###############################################################
#  Generated by:      Cadence Innovus 20.13-s083_1
#  OS:                Linux x86_64(Host ID caddy13)
#  Generated on:      Sun Jul 11 21:08:58 2021
#  Design:            deconv_kernel_estimator_top_level
#  Command:           write_lef_abstract -specifyTopLayer 6 -PGPinLayers {5 6} -noCutObs -stripePin results/deconv_kernel_estimator_top_level.lef
###############################################################

VERSION 5.8 ;

BUSBITCHARS "[]" ;
DIVIDERCHAR "/" ;

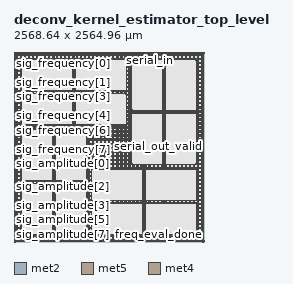
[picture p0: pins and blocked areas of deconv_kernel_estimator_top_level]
MACRO deconv_kernel_estimator_top_level
  CLASS BLOCK ;
  SIZE 2568.640000 BY 2564.960000 ;
  FOREIGN deconv_kernel_estimator_top_level 0.000000 0.000000 ;
  ORIGIN 0 0 ;
  SYMMETRY X Y R90 ;
  PIN clk
    DIRECTION INPUT ;
    USE SIGNAL ;
    ANTENNAPARTIALMETALAREA 6.3938 LAYER met2  ;
    ANTENNAPARTIALMETALSIDEAREA 31.808 LAYER met2  ;
    ANTENNAPARTIALCUTAREA 0.04 LAYER via2  ;
    ANTENNAPARTIALMETALAREA 8.9508 LAYER met3  ;
    ANTENNAPARTIALMETALSIDEAREA 48.208 LAYER met3  ;
    ANTENNAMODEL OXIDE1 ;
    ANTENNAGATEAREA 0.576 LAYER met3  ;
    ANTENNAMAXAREACAR 16.6087 LAYER met3  ;
    ANTENNAMAXSIDEAREACAR 86.8212 LAYER met3  ;
    ANTENNAMAXCUTCAR 0.158681 LAYER via3  ;
    PORT
      LAYER met2 ;
        RECT 1.080000 2564.475000 1.220000 2564.960000 ;
    END
  END clk
  PIN rst_n
    DIRECTION INPUT ;
    USE SIGNAL ;
    ANTENNAPARTIALMETALAREA 73.5824 LAYER met2  ;
    ANTENNAPARTIALMETALSIDEAREA 367.633 LAYER met2  ;
    ANTENNAPARTIALCUTAREA 0.04 LAYER via2  ;
    ANTENNAPARTIALMETALAREA 0.2509 LAYER met3  ;
    ANTENNAPARTIALMETALSIDEAREA 1.808 LAYER met3  ;
    ANTENNAPARTIALCUTAREA 0.04 LAYER via3  ;
    ANTENNAPARTIALMETALAREA 4.3518 LAYER met4  ;
    ANTENNAPARTIALMETALSIDEAREA 23.68 LAYER met4  ;
    ANTENNAMODEL OXIDE1 ;
    ANTENNAGATEAREA 0.495 LAYER met4  ;
    ANTENNAMAXAREACAR 37.3026 LAYER met4  ;
    ANTENNAMAXSIDEAREACAR 189.04 LAYER met4  ;
    ANTENNAMAXCUTCAR 0.265455 LAYER via4  ;
    PORT
      LAYER met2 ;
        RECT 366.780000 2564.475000 366.920000 2564.960000 ;
    END
  END rst_n
  PIN load_en
    DIRECTION INPUT ;
    USE SIGNAL ;
    ANTENNAPARTIALMETALAREA 69.7464 LAYER met2  ;
    ANTENNAPARTIALMETALSIDEAREA 348.453 LAYER met2  ;
    ANTENNAPARTIALCUTAREA 0.04 LAYER via2  ;
    ANTENNAPARTIALMETALAREA 3.505 LAYER met3  ;
    ANTENNAPARTIALMETALSIDEAREA 19.16 LAYER met3  ;
    ANTENNAPARTIALCUTAREA 0.04 LAYER via3  ;
    ANTENNAPARTIALMETALAREA 37.8747 LAYER met4  ;
    ANTENNAPARTIALMETALSIDEAREA 202.464 LAYER met4  ;
    ANTENNAMODEL OXIDE1 ;
    ANTENNAGATEAREA 0.8685 LAYER met4  ;
    ANTENNAMAXAREACAR 58.3144 LAYER met4  ;
    ANTENNAMAXSIDEAREACAR 302.811 LAYER met4  ;
    ANTENNAMAXCUTCAR 1.04286 LAYER via4  ;
    PORT
      LAYER met2 ;
        RECT 733.860000 2564.475000 734.000000 2564.960000 ;
    END
  END load_en
  PIN debug_en
    DIRECTION INPUT ;
    USE SIGNAL ;
    ANTENNAPARTIALMETALAREA 47.3156 LAYER met2  ;
    ANTENNAPARTIALMETALSIDEAREA 236.299 LAYER met2  ;
    ANTENNAPARTIALCUTAREA 0.04 LAYER via2  ;
    ANTENNAPARTIALMETALAREA 1.0656 LAYER met3  ;
    ANTENNAPARTIALMETALSIDEAREA 6.624 LAYER met3  ;
    ANTENNAMODEL OXIDE1 ;
    ANTENNAGATEAREA 0.159 LAYER met3  ;
    ANTENNAMAXAREACAR 18.8909 LAYER met3  ;
    ANTENNAMAXSIDEAREACAR 97.8239 LAYER met3  ;
    ANTENNAMAXCUTCAR 0.574843 LAYER via3  ;
    PORT
      LAYER met2 ;
        RECT 1100.480000 2564.475000 1100.620000 2564.960000 ;
    END
  END debug_en
  PIN serial_in
    DIRECTION INPUT ;
    USE SIGNAL ;
    ANTENNAPARTIALMETALAREA 72.3112 LAYER met2  ;
    ANTENNAPARTIALMETALSIDEAREA 361.277 LAYER met2  ;
    ANTENNAPARTIALCUTAREA 0.04 LAYER via2  ;
    ANTENNAPARTIALMETALAREA 0.255 LAYER met3  ;
    ANTENNAPARTIALMETALSIDEAREA 1.808 LAYER met3  ;
    ANTENNAPARTIALCUTAREA 0.04 LAYER via3  ;
    ANTENNAPARTIALMETALAREA 6.1578 LAYER met4  ;
    ANTENNAPARTIALMETALSIDEAREA 33.312 LAYER met4  ;
    ANTENNAMODEL OXIDE1 ;
    ANTENNAGATEAREA 0.315 LAYER met4  ;
    ANTENNAMAXAREACAR 27.3717 LAYER met4  ;
    ANTENNAMAXSIDEAREACAR 142.159 LAYER met4  ;
    ANTENNAMAXCUTCAR 0.417143 LAYER via4  ;
    PORT
      LAYER met2 ;
        RECT 1834.180000 2564.475000 1834.320000 2564.960000 ;
    END
  END serial_in
  PIN sram_select[1]
    DIRECTION INPUT ;
    USE SIGNAL ;
    ANTENNAPARTIALMETALAREA 151.739 LAYER met2  ;
    ANTENNAPARTIALMETALSIDEAREA 758.415 LAYER met2  ;
    ANTENNAPARTIALCUTAREA 0.04 LAYER via2  ;
    ANTENNAPARTIALMETALAREA 0.255 LAYER met3  ;
    ANTENNAPARTIALMETALSIDEAREA 1.808 LAYER met3  ;
    ANTENNAPARTIALCUTAREA 0.04 LAYER via3  ;
    ANTENNAPARTIALMETALAREA 3.9618 LAYER met4  ;
    ANTENNAPARTIALMETALSIDEAREA 21.6 LAYER met4  ;
    ANTENNAMODEL OXIDE1 ;
    ANTENNAGATEAREA 0.213 LAYER met4  ;
    ANTENNAMAXAREACAR 39.2394 LAYER met4  ;
    ANTENNAMAXSIDEAREACAR 202.122 LAYER met4  ;
    ANTENNAMAXCUTCAR 0.616901 LAYER via4  ;
    PORT
      LAYER met2 ;
        RECT 2567.420000 2564.475000 2567.560000 2564.960000 ;
    END
  END sram_select[1]
  PIN sram_select[0]
    DIRECTION INPUT ;
    USE SIGNAL ;
    ANTENNAPARTIALMETALAREA 94.3528 LAYER met2  ;
    ANTENNAPARTIALMETALSIDEAREA 471.485 LAYER met2  ;
    ANTENNAPARTIALCUTAREA 0.04 LAYER via2  ;
    ANTENNAPARTIALMETALAREA 0.331 LAYER met3  ;
    ANTENNAPARTIALMETALSIDEAREA 2.232 LAYER met3  ;
    ANTENNAPARTIALCUTAREA 0.04 LAYER via3  ;
    ANTENNAPARTIALMETALAREA 4.3518 LAYER met4  ;
    ANTENNAPARTIALMETALSIDEAREA 23.68 LAYER met4  ;
    ANTENNAMODEL OXIDE1 ;
    ANTENNAGATEAREA 0.1965 LAYER met4  ;
    ANTENNAMAXAREACAR 55.8402 LAYER met4  ;
    ANTENNAMAXSIDEAREACAR 288.254 LAYER met4  ;
    ANTENNAMAXCUTCAR 0.668702 LAYER via4  ;
    PORT
      LAYER met2 ;
        RECT 2201.260000 2564.475000 2201.400000 2564.960000 ;
    END
  END sram_select[0]
  PIN frequency_adc_done
    DIRECTION INPUT ;
    USE SIGNAL ;
    ANTENNAPARTIALMETALAREA 132.258 LAYER met2  ;
    ANTENNAPARTIALMETALSIDEAREA 661.013 LAYER met2  ;
    ANTENNAPARTIALCUTAREA 0.04 LAYER via2  ;
    ANTENNAPARTIALMETALAREA 0.4 LAYER met3  ;
    ANTENNAPARTIALMETALSIDEAREA 2.6 LAYER met3  ;
    ANTENNAPARTIALCUTAREA 0.04 LAYER via3  ;
    ANTENNAPARTIALMETALAREA 4.5588 LAYER met4  ;
    ANTENNAPARTIALMETALSIDEAREA 24.784 LAYER met4  ;
    ANTENNAMODEL OXIDE1 ;
    ANTENNAGATEAREA 0.213 LAYER met4  ;
    ANTENNAMAXAREACAR 41.7831 LAYER met4  ;
    ANTENNAMAXSIDEAREACAR 216.089 LAYER met4  ;
    ANTENNAMAXCUTCAR 0.616901 LAYER via4  ;
    PORT
      LAYER met2 ;
        RECT 0.000000 2564.720000 0.485000 2564.860000 ;
    END
  END frequency_adc_done
  PIN amplitude_adc_done
    DIRECTION INPUT ;
    USE SIGNAL ;
    ANTENNAPARTIALMETALAREA 0.133 LAYER met2  ;
    ANTENNAPARTIALMETALSIDEAREA 0.504 LAYER met2  ;
    ANTENNAPARTIALCUTAREA 0.04 LAYER via2  ;
    ANTENNAPARTIALMETALAREA 32.071 LAYER met3  ;
    ANTENNAPARTIALMETALSIDEAREA 171.512 LAYER met3  ;
    ANTENNAPARTIALCUTAREA 0.04 LAYER via3  ;
    ANTENNAPARTIALMETALAREA 1.3924 LAYER met4  ;
    ANTENNAPARTIALMETALSIDEAREA 3.776 LAYER met4  ;
    ANTENNAPARTIALCUTAREA 0.64 LAYER via4  ;
    ANTENNADIFFAREA 2.6082 LAYER met5  ;
    ANTENNAPARTIALMETALAREA 684.832 LAYER met5  ;
    ANTENNAPARTIALMETALSIDEAREA 1031.09 LAYER met5  ;
    ANTENNAMODEL OXIDE1 ;
    ANTENNAGATEAREA 2.7672 LAYER met5  ;
    ANTENNAMAXAREACAR 257.092 LAYER met5  ;
    ANTENNAMAXSIDEAREACAR 402.468 LAYER met5  ;
    PORT
      LAYER met2 ;
        RECT 0.000000 1206.760000 0.485000 1206.900000 ;
    END
  END amplitude_adc_done
  PIN sig_frequency[7]
    DIRECTION INPUT ;
    USE SIGNAL ;
    ANTENNAPARTIALMETALAREA 0.1351 LAYER met2  ;
    ANTENNAPARTIALMETALSIDEAREA 0.5145 LAYER met2  ;
    ANTENNAPARTIALCUTAREA 0.04 LAYER via2  ;
    ANTENNAPARTIALMETALAREA 32.254 LAYER met3  ;
    ANTENNAPARTIALMETALSIDEAREA 172.488 LAYER met3  ;
    ANTENNAPARTIALCUTAREA 0.04 LAYER via3  ;
    ANTENNAPARTIALMETALAREA 2.5558 LAYER met4  ;
    ANTENNAPARTIALMETALSIDEAREA 9.976 LAYER met4  ;
    ANTENNAPARTIALCUTAREA 0.64 LAYER via4  ;
    ANTENNADIFFAREA 2.6082 LAYER met5  ;
    ANTENNAPARTIALMETALAREA 682.624 LAYER met5  ;
    ANTENNAPARTIALMETALSIDEAREA 1027.78 LAYER met5  ;
    ANTENNAMODEL OXIDE1 ;
    ANTENNAGATEAREA 2.7672 LAYER met5  ;
    ANTENNAMAXAREACAR 253.162 LAYER met5  ;
    ANTENNAMAXSIDEAREACAR 384.625 LAYER met5  ;
    PORT
      LAYER met2 ;
        RECT 0.000000 1357.720000 0.485000 1357.860000 ;
    END
  END sig_frequency[7]
  PIN sig_frequency[6]
    DIRECTION INPUT ;
    USE SIGNAL ;
    ANTENNAPARTIALMETALAREA 1.4026 LAYER met2  ;
    ANTENNAPARTIALMETALSIDEAREA 6.734 LAYER met2  ;
    ANTENNAPARTIALCUTAREA 0.04 LAYER via2  ;
    ANTENNAPARTIALMETALAREA 143.665 LAYER met3  ;
    ANTENNAPARTIALMETALSIDEAREA 766.68 LAYER met3  ;
    ANTENNAPARTIALCUTAREA 0.04 LAYER via3  ;
    ANTENNAPARTIALMETALAREA 0.6516 LAYER met4  ;
    ANTENNAPARTIALMETALSIDEAREA 4.416 LAYER met4  ;
    ANTENNAMODEL OXIDE1 ;
    ANTENNAGATEAREA 0.495 LAYER met4  ;
    ANTENNAMAXAREACAR 31.1539 LAYER met4  ;
    ANTENNAMAXSIDEAREACAR 157.504 LAYER met4  ;
    ANTENNAMAXCUTCAR 0.369293 LAYER via4  ;
    PORT
      LAYER met2 ;
        RECT 0.000000 1508.680000 0.485000 1508.820000 ;
    END
  END sig_frequency[6]
  PIN sig_frequency[5]
    DIRECTION INPUT ;
    USE SIGNAL ;
    ANTENNAPARTIALMETALAREA 19.177 LAYER met2  ;
    ANTENNAPARTIALMETALSIDEAREA 95.606 LAYER met2  ;
    ANTENNAPARTIALCUTAREA 0.04 LAYER via2  ;
    ANTENNAPARTIALMETALAREA 7.873 LAYER met3  ;
    ANTENNAPARTIALMETALSIDEAREA 42.456 LAYER met3  ;
    ANTENNAPARTIALCUTAREA 0.04 LAYER via3  ;
    ANTENNAPARTIALMETALAREA 10.7808 LAYER met4  ;
    ANTENNAPARTIALMETALSIDEAREA 57.968 LAYER met4  ;
    ANTENNAMODEL OXIDE1 ;
    ANTENNAGATEAREA 0.495 LAYER met4  ;
    ANTENNAMAXAREACAR 62.6131 LAYER met4  ;
    ANTENNAMAXSIDEAREACAR 327.776 LAYER met4  ;
    ANTENNAMAXCUTCAR 0.369293 LAYER via4  ;
    PORT
      LAYER met2 ;
        RECT 0.000000 1659.300000 0.485000 1659.440000 ;
    END
  END sig_frequency[5]
  PIN sig_frequency[4]
    DIRECTION INPUT ;
    USE SIGNAL ;
    ANTENNAPARTIALMETALAREA 36.747 LAYER met2  ;
    ANTENNAPARTIALMETALSIDEAREA 183.456 LAYER met2  ;
    ANTENNAPARTIALCUTAREA 0.04 LAYER via2  ;
    ANTENNAPARTIALMETALAREA 0.255 LAYER met3  ;
    ANTENNAPARTIALMETALSIDEAREA 1.808 LAYER met3  ;
    ANTENNAPARTIALCUTAREA 0.04 LAYER via3  ;
    ANTENNAPARTIALMETALAREA 5.9748 LAYER met4  ;
    ANTENNAPARTIALMETALSIDEAREA 32.336 LAYER met4  ;
    ANTENNAMODEL OXIDE1 ;
    ANTENNAGATEAREA 0.1965 LAYER met4  ;
    ANTENNAMAXAREACAR 43.9033 LAYER met4  ;
    ANTENNAMAXSIDEAREACAR 225.135 LAYER met4  ;
    ANTENNAMAXCUTCAR 0.668702 LAYER via4  ;
    PORT
      LAYER met2 ;
        RECT 0.000000 1810.260000 0.485000 1810.400000 ;
    END
  END sig_frequency[4]
  PIN sig_frequency[3]
    DIRECTION INPUT ;
    USE SIGNAL ;
    ANTENNAPARTIALMETALAREA 60.4773 LAYER met2  ;
    ANTENNAPARTIALMETALSIDEAREA 301.871 LAYER met2  ;
    ANTENNAPARTIALCUTAREA 0.04 LAYER via2  ;
    ANTENNAPARTIALMETALAREA 72.94 LAYER met3  ;
    ANTENNAPARTIALMETALSIDEAREA 389.48 LAYER met3  ;
    ANTENNAPARTIALCUTAREA 0.04 LAYER via3  ;
    ANTENNAPARTIALMETALAREA 12.9288 LAYER met4  ;
    ANTENNAPARTIALMETALSIDEAREA 69.424 LAYER met4  ;
    ANTENNAMODEL OXIDE1 ;
    ANTENNAGATEAREA 0.495 LAYER met4  ;
    ANTENNAMAXAREACAR 70.4721 LAYER met4  ;
    ANTENNAMAXSIDEAREACAR 367.642 LAYER met4  ;
    ANTENNAMAXCUTCAR 0.450101 LAYER via4  ;
    PORT
      LAYER met2 ;
        RECT 0.000000 1961.220000 0.485000 1961.360000 ;
    END
  END sig_frequency[3]
  PIN sig_frequency[2]
    DIRECTION INPUT ;
    USE SIGNAL ;
    ANTENNAPARTIALMETALAREA 0.5746 LAYER met2  ;
    ANTENNAPARTIALMETALSIDEAREA 2.765 LAYER met2  ;
    ANTENNAMODEL OXIDE1 ;
    ANTENNAGATEAREA 0.159 LAYER met2  ;
    ANTENNAMAXAREACAR 43.3657 LAYER met2  ;
    ANTENNAMAXSIDEAREACAR 212.211 LAYER met2  ;
    ANTENNAMAXCUTCAR 0.32327 LAYER via2  ;
    PORT
      LAYER met2 ;
        RECT 0.000000 2111.840000 0.485000 2111.980000 ;
    END
  END sig_frequency[2]
  PIN sig_frequency[1]
    DIRECTION INPUT ;
    USE SIGNAL ;
    ANTENNAPARTIALMETALAREA 1.0521 LAYER met2  ;
    ANTENNAPARTIALMETALSIDEAREA 5.0995 LAYER met2  ;
    ANTENNAPARTIALCUTAREA 0.04 LAYER via2  ;
    ANTENNAPARTIALMETALAREA 0.255 LAYER met3  ;
    ANTENNAPARTIALMETALSIDEAREA 1.808 LAYER met3  ;
    ANTENNAPARTIALCUTAREA 0.04 LAYER via3  ;
    ANTENNADIFFAREA 0.8694 LAYER met4  ;
    ANTENNAPARTIALMETALAREA 1.9488 LAYER met4  ;
    ANTENNAPARTIALMETALSIDEAREA 10.864 LAYER met4  ;
    ANTENNAMODEL OXIDE1 ;
    ANTENNAGATEAREA 1.0284 LAYER met4  ;
    ANTENNAMAXAREACAR 98.2655 LAYER met4  ;
    ANTENNAMAXSIDEAREACAR 474.81 LAYER met4  ;
    ANTENNAMAXCUTCAR 0.166152 LAYER via4  ;
    PORT
      LAYER met2 ;
        RECT 0.000000 2262.800000 0.485000 2262.940000 ;
    END
  END sig_frequency[1]
  PIN sig_frequency[0]
    DIRECTION INPUT ;
    USE SIGNAL ;
    ANTENNAPARTIALMETALAREA 117 LAYER met2  ;
    ANTENNAPARTIALMETALSIDEAREA 584.721 LAYER met2  ;
    ANTENNAPARTIALCUTAREA 0.04 LAYER via2  ;
    ANTENNAPARTIALMETALAREA 0.255 LAYER met3  ;
    ANTENNAPARTIALMETALSIDEAREA 1.808 LAYER met3  ;
    ANTENNAPARTIALCUTAREA 0.04 LAYER via3  ;
    ANTENNAPARTIALMETALAREA 4.1448 LAYER met4  ;
    ANTENNAPARTIALMETALSIDEAREA 22.576 LAYER met4  ;
    ANTENNAMODEL OXIDE1 ;
    ANTENNAGATEAREA 0.159 LAYER met4  ;
    ANTENNAMAXAREACAR 67.2619 LAYER met4  ;
    ANTENNAMAXSIDEAREACAR 346.528 LAYER met4  ;
    ANTENNAMAXCUTCAR 0.826415 LAYER via4  ;
    PORT
      LAYER met2 ;
        RECT 0.000000 2413.760000 0.485000 2413.900000 ;
    END
  END sig_frequency[0]
  PIN sig_amplitude[7]
    DIRECTION INPUT ;
    USE SIGNAL ;
    ANTENNAPARTIALMETALAREA 12.7036 LAYER met2  ;
    ANTENNAPARTIALMETALSIDEAREA 63.056 LAYER met2  ;
    ANTENNAMODEL OXIDE1 ;
    ANTENNAGATEAREA 0.213 LAYER met2  ;
    ANTENNAMAXAREACAR 65.0117 LAYER met2  ;
    ANTENNAMAXSIDEAREACAR 318.707 LAYER met2  ;
    ANTENNAMAXCUTCAR 0.241315 LAYER via2  ;
    PORT
      LAYER met2 ;
        RECT 0.000000 0.100000 0.485000 0.240000 ;
    END
  END sig_amplitude[7]
  PIN sig_amplitude[6]
    DIRECTION INPUT ;
    USE SIGNAL ;
    ANTENNAPARTIALMETALAREA 149.768 LAYER met2  ;
    ANTENNAPARTIALMETALSIDEAREA 748.681 LAYER met2  ;
    ANTENNAPARTIALCUTAREA 0.04 LAYER via2  ;
    ANTENNAPARTIALMETALAREA 0.2509 LAYER met3  ;
    ANTENNAPARTIALMETALSIDEAREA 1.808 LAYER met3  ;
    ANTENNAPARTIALCUTAREA 0.04 LAYER via3  ;
    ANTENNAPARTIALMETALAREA 4.1448 LAYER met4  ;
    ANTENNAPARTIALMETALSIDEAREA 22.576 LAYER met4  ;
    ANTENNAMODEL OXIDE1 ;
    ANTENNAGATEAREA 0.213 LAYER met4  ;
    ANTENNAMAXAREACAR 55.7883 LAYER met4  ;
    ANTENNAMAXSIDEAREACAR 285.249 LAYER met4  ;
    ANTENNAMAXCUTCAR 0.616901 LAYER via4  ;
    PORT
      LAYER met2 ;
        RECT 0.000000 150.720000 0.485000 150.860000 ;
    END
  END sig_amplitude[6]
  PIN sig_amplitude[5]
    DIRECTION INPUT ;
    USE SIGNAL ;
    ANTENNAPARTIALMETALAREA 2.2882 LAYER met2  ;
    ANTENNAPARTIALMETALSIDEAREA 11.333 LAYER met2  ;
    ANTENNAMODEL OXIDE1 ;
    ANTENNAGATEAREA 0.213 LAYER met2  ;
    ANTENNAMAXAREACAR 41.7883 LAYER met2  ;
    ANTENNAMAXSIDEAREACAR 204.077 LAYER met2  ;
    ANTENNAMAXCUTCAR 0.241315 LAYER via2  ;
    PORT
      LAYER met2 ;
        RECT 0.000000 301.680000 0.485000 301.820000 ;
    END
  END sig_amplitude[5]
  PIN sig_amplitude[4]
    DIRECTION INPUT ;
    USE SIGNAL ;
    ANTENNAPARTIALMETALAREA 102.02 LAYER met2  ;
    ANTENNAPARTIALMETALSIDEAREA 509.821 LAYER met2  ;
    ANTENNAPARTIALCUTAREA 0.04 LAYER via2  ;
    ANTENNAPARTIALMETALAREA 0.255 LAYER met3  ;
    ANTENNAPARTIALMETALSIDEAREA 1.808 LAYER met3  ;
    ANTENNAPARTIALCUTAREA 0.04 LAYER via3  ;
    ANTENNAPARTIALMETALAREA 3.9618 LAYER met4  ;
    ANTENNAPARTIALMETALSIDEAREA 21.6 LAYER met4  ;
    ANTENNAMODEL OXIDE1 ;
    ANTENNAGATEAREA 0.213 LAYER met4  ;
    ANTENNAMAXAREACAR 38.2798 LAYER met4  ;
    ANTENNAMAXSIDEAREACAR 197.324 LAYER met4  ;
    ANTENNAMAXCUTCAR 0.616901 LAYER via4  ;
    PORT
      LAYER met2 ;
        RECT 0.000000 452.640000 0.485000 452.780000 ;
    END
  END sig_amplitude[4]
  PIN sig_amplitude[3]
    DIRECTION INPUT ;
    USE SIGNAL ;
    ANTENNAPARTIALMETALAREA 6.3903 LAYER met2  ;
    ANTENNAPARTIALMETALSIDEAREA 31.7905 LAYER met2  ;
    ANTENNAPARTIALCUTAREA 0.04 LAYER via2  ;
    ANTENNAPARTIALMETALAREA 26.626 LAYER met3  ;
    ANTENNAPARTIALMETALSIDEAREA 142.472 LAYER met3  ;
    ANTENNAPARTIALCUTAREA 0.04 LAYER via3  ;
    ANTENNAPARTIALMETALAREA 2.5558 LAYER met4  ;
    ANTENNAPARTIALMETALSIDEAREA 9.976 LAYER met4  ;
    ANTENNAPARTIALCUTAREA 0.64 LAYER via4  ;
    ANTENNADIFFAREA 2.6082 LAYER met5  ;
    ANTENNAPARTIALMETALAREA 702.496 LAYER met5  ;
    ANTENNAPARTIALMETALSIDEAREA 1057.58 LAYER met5  ;
    ANTENNAMODEL OXIDE1 ;
    ANTENNAGATEAREA 2.8212 LAYER met5  ;
    ANTENNAMAXAREACAR 256.51 LAYER met5  ;
    ANTENNAMAXSIDEAREACAR 393.526 LAYER met5  ;
    PORT
      LAYER met2 ;
        RECT 0.000000 603.260000 0.485000 603.400000 ;
    END
  END sig_amplitude[3]
  PIN sig_amplitude[2]
    DIRECTION INPUT ;
    USE SIGNAL ;
    ANTENNAPARTIALMETALAREA 61.8679 LAYER met2  ;
    ANTENNAPARTIALMETALSIDEAREA 309.061 LAYER met2  ;
    ANTENNAPARTIALCUTAREA 0.04 LAYER via2  ;
    ANTENNAPARTIALMETALAREA 0.255 LAYER met3  ;
    ANTENNAPARTIALMETALSIDEAREA 1.808 LAYER met3  ;
    ANTENNAPARTIALCUTAREA 0.04 LAYER via3  ;
    ANTENNAPARTIALMETALAREA 3.7788 LAYER met4  ;
    ANTENNAPARTIALMETALSIDEAREA 20.624 LAYER met4  ;
    ANTENNAMODEL OXIDE1 ;
    ANTENNAGATEAREA 0.213 LAYER met4  ;
    ANTENNAMAXAREACAR 36.1521 LAYER met4  ;
    ANTENNAMAXSIDEAREACAR 186.399 LAYER met4  ;
    ANTENNAMAXCUTCAR 0.616901 LAYER via4  ;
    PORT
      LAYER met2 ;
        RECT 0.000000 754.220000 0.485000 754.360000 ;
    END
  END sig_amplitude[2]
  PIN sig_amplitude[1]
    DIRECTION INPUT ;
    USE SIGNAL ;
    ANTENNAPARTIALMETALAREA 16.2263 LAYER met2  ;
    ANTENNAPARTIALMETALSIDEAREA 80.7345 LAYER met2  ;
    ANTENNAPARTIALCUTAREA 0.04 LAYER via2  ;
    ANTENNAPARTIALMETALAREA 154.774 LAYER met3  ;
    ANTENNAPARTIALMETALSIDEAREA 825.928 LAYER met3  ;
    ANTENNAPARTIALCUTAREA 0.04 LAYER via3  ;
    ANTENNAPARTIALMETALAREA 25.0648 LAYER met4  ;
    ANTENNAPARTIALMETALSIDEAREA 130.024 LAYER met4  ;
    ANTENNAPARTIALCUTAREA 0.64 LAYER via4  ;
    ANTENNAPARTIALMETALAREA 38.24 LAYER met5  ;
    ANTENNAPARTIALMETALSIDEAREA 65.04 LAYER met5  ;
    ANTENNAMODEL OXIDE1 ;
    ANTENNAGATEAREA 0.1965 LAYER met5  ;
    ANTENNAMAXAREACAR 267.897 LAYER met5  ;
    ANTENNAMAXSIDEAREACAR 700.784 LAYER met5  ;
    PORT
      LAYER met2 ;
        RECT 0.000000 905.180000 0.485000 905.320000 ;
    END
  END sig_amplitude[1]
  PIN sig_amplitude[0]
    DIRECTION INPUT ;
    USE SIGNAL ;
    ANTENNAPARTIALMETALAREA 15.796 LAYER met2  ;
    ANTENNAPARTIALMETALSIDEAREA 78.701 LAYER met2  ;
    ANTENNAPARTIALCUTAREA 0.04 LAYER via2  ;
    ANTENNAPARTIALMETALAREA 26.812 LAYER met3  ;
    ANTENNAPARTIALMETALSIDEAREA 143.464 LAYER met3  ;
    ANTENNAPARTIALCUTAREA 0.04 LAYER via3  ;
    ANTENNAPARTIALMETALAREA 1.3924 LAYER met4  ;
    ANTENNAPARTIALMETALSIDEAREA 3.776 LAYER met4  ;
    ANTENNAPARTIALCUTAREA 0.64 LAYER via4  ;
    ANTENNADIFFAREA 2.6082 LAYER met5  ;
    ANTENNAPARTIALMETALAREA 711.232 LAYER met5  ;
    ANTENNAPARTIALMETALSIDEAREA 1070.69 LAYER met5  ;
    ANTENNAMODEL OXIDE1 ;
    ANTENNAGATEAREA 2.7672 LAYER met5  ;
    ANTENNAMAXAREACAR 264.447 LAYER met5  ;
    ANTENNAMAXSIDEAREACAR 405.11 LAYER met5  ;
    PORT
      LAYER met2 ;
        RECT 0.000000 1055.800000 0.485000 1055.940000 ;
    END
  END sig_amplitude[0]
  PIN adc_bypass_en
    DIRECTION INPUT ;
    USE SIGNAL ;
    ANTENNAPARTIALMETALAREA 45.5446 LAYER met2  ;
    ANTENNAPARTIALMETALSIDEAREA 227.444 LAYER met2  ;
    ANTENNAPARTIALCUTAREA 0.04 LAYER via2  ;
    ANTENNAPARTIALMETALAREA 0.255 LAYER met3  ;
    ANTENNAPARTIALMETALSIDEAREA 1.808 LAYER met3  ;
    ANTENNAPARTIALCUTAREA 0.04 LAYER via3  ;
    ANTENNADIFFAREA 0.4347 LAYER met4  ;
    ANTENNAPARTIALMETALAREA 8.3538 LAYER met4  ;
    ANTENNAPARTIALMETALSIDEAREA 45.024 LAYER met4  ;
    ANTENNAMODEL OXIDE1 ;
    ANTENNAGATEAREA 0.6477 LAYER met4  ;
    ANTENNAMAXAREACAR 61.0385 LAYER met4  ;
    ANTENNAMAXSIDEAREACAR 292.772 LAYER met4  ;
    ANTENNAMAXCUTCAR 0.293933 LAYER via4  ;
    PORT
      LAYER met2 ;
        RECT 1467.560000 2564.475000 1467.700000 2564.960000 ;
    END
  END adc_bypass_en
  PIN serial_out
    DIRECTION OUTPUT ;
    USE SIGNAL ;
    ANTENNADIFFAREA 0.4455 LAYER met2  ;
    ANTENNAPARTIALMETALAREA 91.4218 LAYER met2  ;
    ANTENNAPARTIALMETALSIDEAREA 456.883 LAYER met2  ;
    PORT
      LAYER met2 ;
        RECT 2568.155000 2564.720000 2568.640000 2564.860000 ;
    END
  END serial_out
  PIN serial_out_valid
    DIRECTION OUTPUT ;
    USE SIGNAL ;
    ANTENNAPARTIALMETALAREA 10.8619 LAYER met2  ;
    ANTENNAPARTIALMETALSIDEAREA 54.1485 LAYER met2  ;
    ANTENNAPARTIALCUTAREA 0.04 LAYER via2  ;
    ANTENNAPARTIALMETALAREA 31.933 LAYER met3  ;
    ANTENNAPARTIALMETALSIDEAREA 170.776 LAYER met3  ;
    ANTENNAPARTIALCUTAREA 0.04 LAYER via3  ;
    ANTENNAPARTIALMETALAREA 1.6408 LAYER met4  ;
    ANTENNAPARTIALMETALSIDEAREA 5.096 LAYER met4  ;
    ANTENNAPARTIALCUTAREA 0.64 LAYER via4  ;
    ANTENNADIFFAREA 0.429 LAYER met5  ;
    ANTENNAPARTIALMETALAREA 671.584 LAYER met5  ;
    ANTENNAPARTIALMETALSIDEAREA 1011.22 LAYER met5  ;
    PORT
      LAYER met2 ;
        RECT 2568.155000 1282.580000 2568.640000 1282.720000 ;
    END
  END serial_out_valid
  PIN freq_eval_done
    DIRECTION OUTPUT ;
    USE SIGNAL ;
    ANTENNADIFFAREA 0.7952 LAYER met2  ;
    ANTENNAPARTIALMETALAREA 146.33 LAYER met2  ;
    ANTENNAPARTIALMETALSIDEAREA 731.423 LAYER met2  ;
    PORT
      LAYER met2 ;
        RECT 2568.155000 0.100000 2568.640000 0.240000 ;
    END
  END freq_eval_done
  PIN VSS
    DIRECTION INOUT ;
    USE GROUND ;
    PORT
      LAYER met5 ;
        RECT 2560.480000 2552.720000 2568.640000 2560.880000 ;
    END
    PORT
      LAYER met5 ;
        RECT 0.000000 2552.720000 8.160000 2560.880000 ;
    END
    PORT
      LAYER met5 ;
        RECT 2560.480000 4.080000 2568.640000 12.240000 ;
    END
    PORT
      LAYER met5 ;
        RECT 0.000000 4.080000 8.160000 12.240000 ;
    END
    PORT
      LAYER met4 ;
        RECT 2556.440000 2556.800000 2564.600000 2564.960000 ;
    END
    PORT
      LAYER met4 ;
        RECT 2556.440000 0.000000 2564.600000 8.160000 ;
    END
    PORT
      LAYER met4 ;
        RECT 4.040000 2556.800000 12.200000 2564.960000 ;
    END
    PORT
      LAYER met4 ;
        RECT 4.040000 0.000000 12.200000 8.160000 ;
    END

# P/G power stripe data as pin
    PORT
      LAYER met4 ;
        RECT 558.140000 822.860000 559.940000 1520.360000 ;
        RECT 528.980000 822.860000 530.780000 1520.360000 ;
        RECT 99.840000 822.860000 101.640000 1520.360000 ;
        RECT 81.600000 4.080000 84.960000 2560.880000 ;
        RECT 27.200000 4.080000 30.560000 2560.880000 ;
        RECT 547.020000 4.080000 550.380000 1579.520000 ;
        RECT 4.040000 0.000000 12.200000 2564.960000 ;
        RECT 987.280000 822.860000 989.080000 1520.360000 ;
        RECT 1006.400000 4.080000 1009.760000 1579.520000 ;
        RECT 1278.400000 985.440000 1281.760000 1579.520000 ;
        RECT 1224.000000 985.440000 1227.360000 1579.520000 ;
        RECT 1169.600000 985.440000 1172.960000 1579.520000 ;
        RECT 1115.200000 985.440000 1118.560000 1579.520000 ;
        RECT 1060.800000 985.440000 1064.160000 1579.520000 ;
        RECT 1441.600000 985.440000 1444.960000 1579.520000 ;
        RECT 1387.200000 985.440000 1390.560000 1579.520000 ;
        RECT 1332.800000 985.440000 1336.160000 1579.520000 ;
        RECT 1579.560000 1044.600000 1581.360000 1742.100000 ;
        RECT 1550.400000 985.440000 1553.760000 2560.880000 ;
        RECT 1496.000000 985.440000 1499.360000 1579.520000 ;
        RECT 2467.000000 1044.600000 2468.800000 1742.100000 ;
        RECT 2037.860000 1044.600000 2039.660000 1742.100000 ;
        RECT 2008.700000 1044.600000 2010.500000 1742.100000 ;
        RECT 2529.600000 4.080000 2532.960000 2560.880000 ;
        RECT 2475.200000 4.080000 2478.560000 2560.880000 ;
        RECT 2027.520000 985.440000 2030.880000 2560.880000 ;
        RECT 2556.440000 0.000000 2564.600000 2564.960000 ;
        RECT 987.280000 98.000000 989.080000 795.500000 ;
        RECT 558.140000 98.000000 559.940000 795.500000 ;
        RECT 528.980000 98.000000 530.780000 795.500000 ;
        RECT 99.840000 98.000000 101.640000 795.500000 ;
        RECT 1046.440000 556.300000 1048.240000 987.240000 ;
        RECT 136.000000 4.080000 139.360000 99.800000 ;
        RECT 299.200000 4.080000 302.560000 99.800000 ;
        RECT 244.800000 4.080000 248.160000 99.800000 ;
        RECT 190.400000 4.080000 193.760000 99.800000 ;
        RECT 462.400000 4.080000 465.760000 99.800000 ;
        RECT 408.000000 4.080000 411.360000 99.800000 ;
        RECT 353.600000 4.080000 356.960000 99.800000 ;
        RECT 625.600000 4.080000 628.960000 99.800000 ;
        RECT 571.200000 4.080000 574.560000 99.800000 ;
        RECT 516.800000 4.080000 520.160000 99.800000 ;
        RECT 1046.440000 98.000000 1048.240000 528.940000 ;
        RECT 788.800000 4.080000 792.160000 99.800000 ;
        RECT 734.400000 4.080000 737.760000 99.800000 ;
        RECT 680.000000 4.080000 683.360000 99.800000 ;
        RECT 952.000000 4.080000 955.360000 99.800000 ;
        RECT 897.600000 4.080000 900.960000 99.800000 ;
        RECT 843.200000 4.080000 846.560000 99.800000 ;
        RECT 813.520000 4.080000 816.880000 99.800000 ;
        RECT 1115.200000 4.080000 1118.560000 99.800000 ;
        RECT 1060.800000 4.080000 1064.160000 99.800000 ;
        RECT 1278.400000 4.080000 1281.760000 99.800000 ;
        RECT 1224.000000 4.080000 1227.360000 99.800000 ;
        RECT 1169.600000 4.080000 1172.960000 99.800000 ;
        RECT 1060.800000 527.140000 1064.160000 558.100000 ;
        RECT 1115.200000 527.140000 1118.560000 558.100000 ;
        RECT 1169.600000 527.140000 1172.960000 558.100000 ;
        RECT 1224.000000 527.140000 1227.360000 558.100000 ;
        RECT 1278.400000 527.140000 1281.760000 558.100000 ;
        RECT 299.200000 793.700000 302.560000 824.660000 ;
        RECT 244.800000 793.700000 248.160000 824.660000 ;
        RECT 190.400000 793.700000 193.760000 824.660000 ;
        RECT 136.000000 793.700000 139.360000 824.660000 ;
        RECT 462.400000 793.700000 465.760000 824.660000 ;
        RECT 353.600000 793.700000 356.960000 824.660000 ;
        RECT 408.000000 793.700000 411.360000 824.660000 ;
        RECT 625.600000 793.700000 628.960000 824.660000 ;
        RECT 571.200000 793.700000 574.560000 824.660000 ;
        RECT 516.800000 793.700000 520.160000 824.660000 ;
        RECT 680.000000 793.700000 683.360000 824.660000 ;
        RECT 734.400000 793.700000 737.760000 824.660000 ;
        RECT 788.800000 793.700000 792.160000 824.660000 ;
        RECT 813.520000 793.700000 816.880000 824.660000 ;
        RECT 843.200000 793.700000 846.560000 824.660000 ;
        RECT 897.600000 793.700000 900.960000 824.660000 ;
        RECT 952.000000 793.700000 955.360000 824.660000 ;
        RECT 2467.000000 556.300000 2468.800000 987.240000 ;
        RECT 1771.300000 556.300000 1773.100000 987.240000 ;
        RECT 1742.140000 556.300000 1743.940000 987.240000 ;
        RECT 1760.520000 4.080000 1763.880000 1046.400000 ;
        RECT 1771.300000 98.000000 1773.100000 528.940000 ;
        RECT 1742.140000 98.000000 1743.940000 528.940000 ;
        RECT 1604.800000 4.080000 1608.160000 99.800000 ;
        RECT 1441.600000 4.080000 1444.960000 99.800000 ;
        RECT 1387.200000 4.080000 1390.560000 99.800000 ;
        RECT 1332.800000 4.080000 1336.160000 99.800000 ;
        RECT 1550.400000 4.080000 1553.760000 99.800000 ;
        RECT 1496.000000 4.080000 1499.360000 99.800000 ;
        RECT 1713.600000 4.080000 1716.960000 99.800000 ;
        RECT 1659.200000 4.080000 1662.560000 99.800000 ;
        RECT 1768.000000 4.080000 1771.360000 99.800000 ;
        RECT 1822.400000 4.080000 1825.760000 99.800000 ;
        RECT 1876.800000 4.080000 1880.160000 99.800000 ;
        RECT 1604.800000 527.140000 1608.160000 558.100000 ;
        RECT 1441.600000 527.140000 1444.960000 558.100000 ;
        RECT 1332.800000 527.140000 1336.160000 558.100000 ;
        RECT 1387.200000 527.140000 1390.560000 558.100000 ;
        RECT 1496.000000 527.140000 1499.360000 558.100000 ;
        RECT 1550.400000 527.140000 1553.760000 558.100000 ;
        RECT 1659.200000 527.140000 1662.560000 558.100000 ;
        RECT 1713.600000 527.140000 1716.960000 558.100000 ;
        RECT 1768.000000 527.140000 1771.360000 558.100000 ;
        RECT 1822.400000 527.140000 1825.760000 558.100000 ;
        RECT 1876.800000 527.140000 1880.160000 558.100000 ;
        RECT 2467.000000 98.000000 2468.800000 528.940000 ;
        RECT 2040.000000 4.080000 2043.360000 99.800000 ;
        RECT 2027.520000 4.080000 2030.880000 99.800000 ;
        RECT 1985.600000 4.080000 1988.960000 99.800000 ;
        RECT 1931.200000 4.080000 1934.560000 99.800000 ;
        RECT 2203.200000 4.080000 2206.560000 99.800000 ;
        RECT 2148.800000 4.080000 2152.160000 99.800000 ;
        RECT 2094.400000 4.080000 2097.760000 99.800000 ;
        RECT 2312.000000 4.080000 2315.360000 99.800000 ;
        RECT 2257.600000 4.080000 2260.960000 99.800000 ;
        RECT 2366.400000 4.080000 2369.760000 99.800000 ;
        RECT 2420.800000 4.080000 2424.160000 99.800000 ;
        RECT 1931.200000 527.140000 1934.560000 558.100000 ;
        RECT 1985.600000 527.140000 1988.960000 558.100000 ;
        RECT 2040.000000 527.140000 2043.360000 558.100000 ;
        RECT 2027.520000 527.140000 2030.880000 558.100000 ;
        RECT 2094.400000 527.140000 2097.760000 558.100000 ;
        RECT 2148.800000 527.140000 2152.160000 558.100000 ;
        RECT 2203.200000 527.140000 2206.560000 558.100000 ;
        RECT 2257.600000 527.140000 2260.960000 558.100000 ;
        RECT 2312.000000 527.140000 2315.360000 558.100000 ;
        RECT 2366.400000 527.140000 2369.760000 558.100000 ;
        RECT 2420.800000 527.140000 2424.160000 558.100000 ;
        RECT 1604.800000 985.440000 1608.160000 1046.400000 ;
        RECT 1659.200000 985.440000 1662.560000 1046.400000 ;
        RECT 1713.600000 985.440000 1716.960000 1046.400000 ;
        RECT 1768.000000 985.440000 1771.360000 1046.400000 ;
        RECT 1822.400000 985.440000 1825.760000 1046.400000 ;
        RECT 1876.800000 985.440000 1880.160000 1046.400000 ;
        RECT 2040.000000 985.440000 2043.360000 1042.200000 ;
        RECT 1931.200000 985.440000 1934.560000 1046.400000 ;
        RECT 1985.600000 985.440000 1988.960000 1046.400000 ;
        RECT 2203.200000 985.440000 2206.560000 1046.400000 ;
        RECT 2148.800000 985.440000 2152.160000 1046.400000 ;
        RECT 2094.400000 985.440000 2097.760000 1046.400000 ;
        RECT 2366.400000 985.440000 2369.760000 1046.400000 ;
        RECT 2312.000000 985.440000 2315.360000 1046.400000 ;
        RECT 2257.600000 985.440000 2260.960000 1046.400000 ;
        RECT 2420.800000 985.440000 2424.160000 1046.400000 ;
        RECT 824.700000 1577.720000 826.500000 2008.660000 ;
        RECT 795.540000 1577.720000 797.340000 2008.660000 ;
        RECT 99.840000 1577.720000 101.640000 2008.660000 ;
        RECT 813.520000 1518.560000 816.880000 2560.880000 ;
        RECT 136.000000 1518.560000 139.360000 1579.520000 ;
        RECT 190.400000 1518.560000 193.760000 1579.520000 ;
        RECT 244.800000 1518.560000 248.160000 1579.520000 ;
        RECT 299.200000 1518.560000 302.560000 1579.520000 ;
        RECT 353.600000 1518.560000 356.960000 1579.520000 ;
        RECT 408.000000 1518.560000 411.360000 1579.520000 ;
        RECT 462.400000 1518.560000 465.760000 1579.520000 ;
        RECT 625.600000 1518.560000 628.960000 1579.520000 ;
        RECT 571.200000 1518.560000 574.560000 1579.520000 ;
        RECT 516.800000 1518.560000 520.160000 1579.520000 ;
        RECT 788.800000 1518.560000 792.160000 1579.520000 ;
        RECT 734.400000 1518.560000 737.760000 1579.520000 ;
        RECT 680.000000 1518.560000 683.360000 1579.520000 ;
        RECT 952.000000 1518.560000 955.360000 1579.520000 ;
        RECT 897.600000 1518.560000 900.960000 1579.520000 ;
        RECT 843.200000 1518.560000 846.560000 1579.520000 ;
        RECT 99.840000 2036.020000 101.640000 2466.960000 ;
        RECT 136.000000 2006.860000 139.360000 2037.820000 ;
        RECT 190.400000 2006.860000 193.760000 2037.820000 ;
        RECT 244.800000 2006.860000 248.160000 2037.820000 ;
        RECT 299.200000 2006.860000 302.560000 2037.820000 ;
        RECT 353.600000 2006.860000 356.960000 2037.820000 ;
        RECT 408.000000 2006.860000 411.360000 2037.820000 ;
        RECT 462.400000 2006.860000 465.760000 2037.820000 ;
        RECT 516.800000 2006.860000 520.160000 2037.820000 ;
        RECT 547.020000 2006.860000 550.380000 2037.820000 ;
        RECT 571.200000 2006.860000 574.560000 2037.820000 ;
        RECT 625.600000 2006.860000 628.960000 2037.820000 ;
        RECT 136.000000 2465.160000 139.360000 2560.880000 ;
        RECT 299.200000 2465.160000 302.560000 2560.880000 ;
        RECT 244.800000 2465.160000 248.160000 2560.880000 ;
        RECT 190.400000 2465.160000 193.760000 2560.880000 ;
        RECT 462.400000 2465.160000 465.760000 2560.880000 ;
        RECT 408.000000 2465.160000 411.360000 2560.880000 ;
        RECT 353.600000 2465.160000 356.960000 2560.880000 ;
        RECT 571.200000 2465.160000 574.560000 2560.880000 ;
        RECT 547.020000 2465.160000 550.380000 2560.880000 ;
        RECT 516.800000 2465.160000 520.160000 2560.880000 ;
        RECT 625.600000 2465.160000 628.960000 2560.880000 ;
        RECT 824.700000 2036.020000 826.500000 2466.960000 ;
        RECT 795.540000 2036.020000 797.340000 2466.960000 ;
        RECT 680.000000 2006.860000 683.360000 2037.820000 ;
        RECT 734.400000 2006.860000 737.760000 2037.820000 ;
        RECT 788.800000 2006.860000 792.160000 2037.820000 ;
        RECT 843.200000 2006.860000 846.560000 2037.820000 ;
        RECT 897.600000 2006.860000 900.960000 2037.820000 ;
        RECT 952.000000 2006.860000 955.360000 2037.820000 ;
        RECT 1006.400000 2006.860000 1009.760000 2037.820000 ;
        RECT 1060.800000 2006.860000 1064.160000 2037.820000 ;
        RECT 1115.200000 2006.860000 1118.560000 2037.820000 ;
        RECT 1169.600000 2006.860000 1172.960000 2037.820000 ;
        RECT 1224.000000 2006.860000 1227.360000 2037.820000 ;
        RECT 1278.400000 2006.860000 1281.760000 2037.820000 ;
        RECT 788.800000 2465.160000 792.160000 2560.880000 ;
        RECT 734.400000 2465.160000 737.760000 2560.880000 ;
        RECT 680.000000 2465.160000 683.360000 2560.880000 ;
        RECT 952.000000 2465.160000 955.360000 2560.880000 ;
        RECT 897.600000 2465.160000 900.960000 2560.880000 ;
        RECT 843.200000 2465.160000 846.560000 2560.880000 ;
        RECT 1115.200000 2465.160000 1118.560000 2560.880000 ;
        RECT 1060.800000 2465.160000 1064.160000 2560.880000 ;
        RECT 1006.400000 2465.160000 1009.760000 2560.880000 ;
        RECT 1169.600000 2465.160000 1172.960000 2560.880000 ;
        RECT 1224.000000 2465.160000 1227.360000 2560.880000 ;
        RECT 1278.400000 2465.160000 1281.760000 2560.880000 ;
        RECT 2467.000000 1769.460000 2468.800000 2466.960000 ;
        RECT 2037.860000 1769.460000 2039.660000 2466.960000 ;
        RECT 2008.700000 1769.460000 2010.500000 2466.960000 ;
        RECT 1579.560000 1769.460000 1581.360000 2466.960000 ;
        RECT 1520.400000 1577.720000 1522.200000 2008.660000 ;
        RECT 1604.800000 1740.300000 1608.160000 1771.260000 ;
        RECT 1659.200000 1740.300000 1662.560000 1771.260000 ;
        RECT 1713.600000 1740.300000 1716.960000 1771.260000 ;
        RECT 1760.520000 1740.300000 1763.880000 1771.260000 ;
        RECT 1768.000000 1740.300000 1771.360000 1771.260000 ;
        RECT 1822.400000 1740.300000 1825.760000 1771.260000 ;
        RECT 1876.800000 1740.300000 1880.160000 1771.260000 ;
        RECT 2203.200000 1740.300000 2206.560000 1771.260000 ;
        RECT 2148.800000 1740.300000 2152.160000 1771.260000 ;
        RECT 2094.400000 1740.300000 2097.760000 1771.260000 ;
        RECT 1985.600000 1740.300000 1988.960000 1771.260000 ;
        RECT 1931.200000 1740.300000 1934.560000 1771.260000 ;
        RECT 2040.000000 1754.400000 2043.360000 1757.770000 ;
        RECT 2312.000000 1740.300000 2315.360000 1771.260000 ;
        RECT 2257.600000 1740.300000 2260.960000 1771.260000 ;
        RECT 2366.400000 1740.300000 2369.760000 1771.260000 ;
        RECT 2420.800000 1740.300000 2424.160000 1771.260000 ;
        RECT 1520.400000 2036.020000 1522.200000 2466.960000 ;
        RECT 1441.600000 2006.860000 1444.960000 2037.820000 ;
        RECT 1332.800000 2006.860000 1336.160000 2037.820000 ;
        RECT 1387.200000 2006.860000 1390.560000 2037.820000 ;
        RECT 1496.000000 2006.860000 1499.360000 2037.820000 ;
        RECT 1604.800000 2465.160000 1608.160000 2560.880000 ;
        RECT 1441.600000 2465.160000 1444.960000 2560.880000 ;
        RECT 1387.200000 2465.160000 1390.560000 2560.880000 ;
        RECT 1332.800000 2465.160000 1336.160000 2560.880000 ;
        RECT 1496.000000 2465.160000 1499.360000 2560.880000 ;
        RECT 1760.520000 2465.160000 1763.880000 2560.880000 ;
        RECT 1713.600000 2465.160000 1716.960000 2560.880000 ;
        RECT 1659.200000 2465.160000 1662.560000 2560.880000 ;
        RECT 1876.800000 2465.160000 1880.160000 2560.880000 ;
        RECT 1822.400000 2465.160000 1825.760000 2560.880000 ;
        RECT 1768.000000 2465.160000 1771.360000 2560.880000 ;
        RECT 1985.600000 2465.160000 1988.960000 2560.880000 ;
        RECT 1931.200000 2465.160000 1934.560000 2560.880000 ;
        RECT 2040.000000 2469.360000 2043.360000 2560.880000 ;
        RECT 2203.200000 2465.160000 2206.560000 2560.880000 ;
        RECT 2148.800000 2465.160000 2152.160000 2560.880000 ;
        RECT 2094.400000 2465.160000 2097.760000 2560.880000 ;
        RECT 2366.400000 2465.160000 2369.760000 2560.880000 ;
        RECT 2312.000000 2465.160000 2315.360000 2560.880000 ;
        RECT 2257.600000 2465.160000 2260.960000 2560.880000 ;
        RECT 2420.800000 2465.160000 2424.160000 2560.880000 ;
        RECT 108.400000 785.200000 110.140000 786.940000 ;
        RECT 978.780000 785.200000 980.520000 786.940000 ;
        RECT 1733.640000 106.560000 1735.380000 108.300000 ;
        RECT 1768.000000 98.000000 1773.100000 99.800000 ;
        RECT 1733.640000 564.860000 1735.380000 566.600000 ;
        RECT 1768.000000 556.300000 1773.100000 558.100000 ;
        RECT 1768.000000 527.140000 1773.100000 528.940000 ;
        RECT 2458.500000 106.560000 2460.240000 108.300000 ;
        RECT 1768.000000 985.440000 1773.100000 987.240000 ;
        RECT 2000.200000 1053.160000 2001.940000 1054.900000 ;
        RECT 2458.500000 976.940000 2460.240000 978.680000 ;
        RECT 2458.500000 1053.160000 2460.240000 1054.900000 ;
        RECT 108.400000 1510.060000 110.140000 1511.800000 ;
        RECT 978.780000 1510.060000 980.520000 1511.800000 ;
        RECT 108.400000 1998.360000 110.140000 2000.100000 ;
        RECT 108.400000 2456.660000 110.140000 2458.400000 ;
        RECT 833.260000 1998.360000 835.000000 2000.100000 ;
        RECT 2458.500000 1778.020000 2460.240000 1779.760000 ;
        RECT 1511.900000 2456.660000 1513.640000 2458.400000 ;
        RECT 2000.200000 2456.660000 2001.940000 2458.400000 ;
      LAYER met5 ;
        RECT 4.040000 68.000000 2564.600000 71.360000 ;
        RECT 0.000000 4.080000 2568.640000 12.240000 ;
        RECT 1046.440000 98.000000 1743.940000 99.800000 ;
        RECT 1046.440000 527.140000 1743.940000 528.940000 ;
        RECT 1046.440000 556.300000 1743.940000 558.100000 ;
        RECT 987.280000 992.800000 2564.600000 996.160000 ;
        RECT 1046.440000 985.440000 1743.940000 987.240000 ;
        RECT 987.280000 1047.200000 1553.765000 1050.560000 ;
        RECT 987.280000 1101.600000 1581.360000 1104.960000 ;
        RECT 987.280000 1156.000000 1581.360000 1159.360000 ;
        RECT 987.280000 1210.400000 1581.360000 1213.760000 ;
        RECT 987.280000 1264.800000 1581.360000 1268.160000 ;
        RECT 558.140000 98.000000 989.080000 99.800000 ;
        RECT 99.840000 98.000000 530.780000 99.800000 ;
        RECT 4.040000 122.400000 101.640000 125.760000 ;
        RECT 4.040000 176.800000 101.640000 180.160000 ;
        RECT 4.040000 231.200000 101.640000 234.560000 ;
        RECT 4.040000 285.600000 101.640000 288.960000 ;
        RECT 528.980000 122.400000 559.940000 125.760000 ;
        RECT 528.980000 176.800000 559.940000 180.160000 ;
        RECT 528.980000 231.200000 559.940000 234.560000 ;
        RECT 528.980000 285.600000 559.940000 288.960000 ;
        RECT 4.040000 340.000000 101.640000 343.360000 ;
        RECT 4.040000 394.400000 101.640000 397.760000 ;
        RECT 4.040000 448.800000 101.640000 452.160000 ;
        RECT 4.040000 557.600000 101.640000 560.960000 ;
        RECT 4.040000 503.200000 101.640000 506.560000 ;
        RECT 4.040000 612.000000 101.640000 615.360000 ;
        RECT 528.980000 340.000000 559.940000 343.360000 ;
        RECT 528.980000 394.400000 559.940000 397.760000 ;
        RECT 528.980000 448.800000 559.940000 452.160000 ;
        RECT 528.980000 557.600000 559.940000 560.960000 ;
        RECT 528.980000 503.200000 559.940000 506.560000 ;
        RECT 528.980000 612.000000 559.940000 615.360000 ;
        RECT 987.280000 122.400000 1048.240000 125.760000 ;
        RECT 987.280000 176.800000 1048.240000 180.160000 ;
        RECT 987.280000 231.200000 1048.240000 234.560000 ;
        RECT 987.280000 285.600000 1048.240000 288.960000 ;
        RECT 987.280000 340.000000 1048.240000 343.360000 ;
        RECT 987.280000 394.400000 1048.240000 397.760000 ;
        RECT 987.280000 448.800000 1048.240000 452.160000 ;
        RECT 987.280000 557.600000 1048.240000 560.960000 ;
        RECT 987.280000 503.200000 1048.240000 506.560000 ;
        RECT 987.280000 612.000000 1048.240000 615.360000 ;
        RECT 558.140000 822.860000 989.080000 824.660000 ;
        RECT 558.140000 793.700000 989.080000 795.500000 ;
        RECT 99.840000 822.860000 530.780000 824.660000 ;
        RECT 99.840000 793.700000 530.780000 795.500000 ;
        RECT 4.040000 666.400000 101.640000 669.760000 ;
        RECT 4.040000 720.800000 101.640000 724.160000 ;
        RECT 4.040000 775.200000 101.640000 778.560000 ;
        RECT 99.840000 785.200000 109.270000 786.940000 ;
        RECT 4.040000 829.600000 101.640000 832.960000 ;
        RECT 4.040000 884.000000 101.640000 887.360000 ;
        RECT 4.040000 938.400000 101.640000 941.760000 ;
        RECT 528.980000 666.400000 559.940000 669.760000 ;
        RECT 528.980000 720.800000 559.940000 724.160000 ;
        RECT 528.980000 775.200000 559.940000 778.560000 ;
        RECT 528.980000 829.600000 559.940000 832.960000 ;
        RECT 528.980000 884.000000 559.940000 887.360000 ;
        RECT 528.980000 938.400000 559.940000 941.760000 ;
        RECT 4.040000 992.800000 101.640000 996.160000 ;
        RECT 4.040000 1047.200000 101.640000 1050.560000 ;
        RECT 4.040000 1101.600000 101.640000 1104.960000 ;
        RECT 4.040000 1156.000000 101.640000 1159.360000 ;
        RECT 4.040000 1210.400000 101.640000 1213.760000 ;
        RECT 4.040000 1264.800000 101.640000 1268.160000 ;
        RECT 528.980000 992.800000 559.940000 996.160000 ;
        RECT 528.980000 1047.200000 559.940000 1050.560000 ;
        RECT 528.980000 1101.600000 559.940000 1104.960000 ;
        RECT 528.980000 1156.000000 559.940000 1159.360000 ;
        RECT 528.980000 1210.400000 559.940000 1213.760000 ;
        RECT 528.980000 1264.800000 559.940000 1268.160000 ;
        RECT 987.280000 666.400000 1048.240000 669.760000 ;
        RECT 987.280000 775.200000 1048.240000 778.560000 ;
        RECT 987.280000 720.800000 1048.240000 724.160000 ;
        RECT 979.650000 785.200000 989.080000 786.940000 ;
        RECT 987.280000 829.600000 1048.240000 832.960000 ;
        RECT 987.280000 938.400000 1048.240000 941.760000 ;
        RECT 987.280000 884.000000 1048.240000 887.360000 ;
        RECT 1771.300000 556.300000 2468.800000 558.100000 ;
        RECT 1771.300000 527.140000 2468.800000 528.940000 ;
        RECT 1771.300000 98.000000 2468.800000 99.800000 ;
        RECT 1742.140000 122.400000 1773.100000 125.760000 ;
        RECT 1734.310000 106.560000 1743.940000 108.300000 ;
        RECT 1742.140000 176.800000 1773.100000 180.160000 ;
        RECT 1742.140000 231.200000 1773.100000 234.560000 ;
        RECT 1742.140000 285.600000 1773.100000 288.960000 ;
        RECT 1742.140000 340.000000 1773.100000 343.360000 ;
        RECT 1742.140000 394.400000 1773.100000 397.760000 ;
        RECT 1742.140000 448.800000 1773.100000 452.160000 ;
        RECT 1742.140000 557.600000 1773.100000 560.960000 ;
        RECT 1742.140000 503.200000 1773.100000 506.560000 ;
        RECT 1742.140000 612.000000 1773.100000 615.360000 ;
        RECT 1734.310000 564.860000 1743.940000 566.600000 ;
        RECT 2467.000000 122.400000 2564.600000 125.760000 ;
        RECT 2459.170000 106.560000 2468.800000 108.300000 ;
        RECT 2467.000000 176.800000 2564.600000 180.160000 ;
        RECT 2467.000000 231.200000 2564.600000 234.560000 ;
        RECT 2467.000000 285.600000 2564.600000 288.960000 ;
        RECT 2467.000000 340.000000 2564.600000 343.360000 ;
        RECT 2467.000000 394.400000 2564.600000 397.760000 ;
        RECT 2467.000000 448.800000 2564.600000 452.160000 ;
        RECT 2467.000000 557.600000 2564.600000 560.960000 ;
        RECT 2467.000000 503.200000 2564.600000 506.560000 ;
        RECT 2467.000000 612.000000 2564.600000 615.360000 ;
        RECT 1771.300000 985.440000 2468.800000 987.240000 ;
        RECT 1579.560000 1044.600000 2010.500000 1046.400000 ;
        RECT 1742.140000 666.400000 1773.100000 669.760000 ;
        RECT 1742.140000 720.800000 1773.100000 724.160000 ;
        RECT 1742.140000 775.200000 1773.100000 778.560000 ;
        RECT 1742.140000 829.600000 1773.100000 832.960000 ;
        RECT 1742.140000 884.000000 1773.100000 887.360000 ;
        RECT 1742.140000 938.400000 1773.100000 941.760000 ;
        RECT 2467.000000 666.400000 2564.600000 669.760000 ;
        RECT 2467.000000 720.800000 2564.600000 724.160000 ;
        RECT 2467.000000 775.200000 2564.600000 778.560000 ;
        RECT 2467.000000 829.600000 2564.600000 832.960000 ;
        RECT 2467.000000 884.000000 2564.600000 887.360000 ;
        RECT 2467.000000 938.400000 2564.600000 941.760000 ;
        RECT 2037.860000 1044.600000 2468.800000 1046.400000 ;
        RECT 2001.070000 1053.160000 2010.500000 1054.900000 ;
        RECT 2008.700000 1101.600000 2039.660000 1104.960000 ;
        RECT 2008.700000 1156.000000 2039.660000 1159.360000 ;
        RECT 2008.700000 1210.400000 2039.660000 1213.760000 ;
        RECT 2008.700000 1264.800000 2039.660000 1268.160000 ;
        RECT 2459.170000 976.940000 2468.800000 978.680000 ;
        RECT 2475.200000 1047.200000 2564.600000 1050.560000 ;
        RECT 2467.000000 1101.600000 2564.600000 1104.960000 ;
        RECT 2459.370000 1053.160000 2468.800000 1054.900000 ;
        RECT 2467.000000 1156.000000 2564.600000 1159.360000 ;
        RECT 2467.000000 1210.400000 2564.600000 1213.760000 ;
        RECT 2467.000000 1264.800000 2564.600000 1268.160000 ;
        RECT 987.280000 1319.200000 1581.360000 1322.560000 ;
        RECT 987.280000 1373.600000 1581.360000 1376.960000 ;
        RECT 987.280000 1428.000000 1581.360000 1431.360000 ;
        RECT 987.280000 1482.400000 1581.360000 1485.760000 ;
        RECT 4.040000 1536.800000 1581.360000 1540.160000 ;
        RECT 824.700000 1577.720000 1522.200000 1579.520000 ;
        RECT 4.040000 2026.400000 1581.360000 2029.760000 ;
        RECT 824.700000 2006.860000 1522.200000 2008.660000 ;
        RECT 824.700000 2036.020000 1522.200000 2037.820000 ;
        RECT 824.700000 2465.160000 1522.200000 2466.960000 ;
        RECT 4.040000 2516.000000 2564.600000 2519.360000 ;
        RECT 0.000000 2552.720000 2568.640000 2560.880000 ;
        RECT 558.140000 1518.560000 989.080000 1520.360000 ;
        RECT 99.840000 1577.720000 797.340000 1579.520000 ;
        RECT 99.840000 1518.560000 530.780000 1520.360000 ;
        RECT 4.040000 1319.200000 101.640000 1322.560000 ;
        RECT 4.040000 1373.600000 101.640000 1376.960000 ;
        RECT 4.040000 1428.000000 101.640000 1431.360000 ;
        RECT 4.040000 1482.400000 101.640000 1485.760000 ;
        RECT 99.840000 1510.060000 109.270000 1511.800000 ;
        RECT 4.040000 1591.200000 101.640000 1594.560000 ;
        RECT 528.980000 1319.200000 559.940000 1322.560000 ;
        RECT 528.980000 1373.600000 559.940000 1376.960000 ;
        RECT 528.980000 1428.000000 559.940000 1431.360000 ;
        RECT 528.980000 1482.400000 559.940000 1485.760000 ;
        RECT 4.040000 1645.600000 101.640000 1648.960000 ;
        RECT 4.040000 1700.000000 101.640000 1703.360000 ;
        RECT 4.040000 1754.400000 101.640000 1757.760000 ;
        RECT 4.040000 1808.800000 101.640000 1812.160000 ;
        RECT 4.040000 1863.200000 101.640000 1866.560000 ;
        RECT 4.040000 1917.600000 101.640000 1920.960000 ;
        RECT 795.540000 1591.200000 826.500000 1594.560000 ;
        RECT 979.650000 1510.060000 989.080000 1511.800000 ;
        RECT 795.540000 1645.600000 826.500000 1648.960000 ;
        RECT 795.540000 1700.000000 826.500000 1703.360000 ;
        RECT 795.540000 1754.400000 826.500000 1757.760000 ;
        RECT 795.540000 1808.800000 826.500000 1812.160000 ;
        RECT 795.540000 1863.200000 826.500000 1866.560000 ;
        RECT 795.540000 1917.600000 826.500000 1920.960000 ;
        RECT 99.840000 2006.860000 797.340000 2008.660000 ;
        RECT 99.840000 2036.020000 797.340000 2037.820000 ;
        RECT 99.840000 2465.160000 797.340000 2466.960000 ;
        RECT 4.040000 2244.000000 101.640000 2247.360000 ;
        RECT 4.040000 1972.000000 101.640000 1975.360000 ;
        RECT 99.840000 1998.360000 109.470000 2000.100000 ;
        RECT 4.040000 2080.800000 101.640000 2084.160000 ;
        RECT 4.040000 2135.200000 101.640000 2138.560000 ;
        RECT 4.040000 2189.600000 101.640000 2192.960000 ;
        RECT 4.040000 2298.400000 101.640000 2301.760000 ;
        RECT 4.040000 2352.800000 101.640000 2356.160000 ;
        RECT 4.040000 2407.200000 101.640000 2410.560000 ;
        RECT 4.040000 2461.600000 84.955000 2464.960000 ;
        RECT 99.840000 2456.660000 109.470000 2458.400000 ;
        RECT 795.540000 2244.000000 826.500000 2247.360000 ;
        RECT 795.540000 1972.000000 826.500000 1975.360000 ;
        RECT 795.540000 2080.800000 826.500000 2084.160000 ;
        RECT 824.700000 1998.360000 834.330000 2000.100000 ;
        RECT 795.540000 2135.200000 826.500000 2138.560000 ;
        RECT 795.540000 2189.600000 826.500000 2192.960000 ;
        RECT 795.540000 2298.400000 826.500000 2301.760000 ;
        RECT 795.540000 2352.800000 826.500000 2356.160000 ;
        RECT 795.540000 2407.200000 826.500000 2410.560000 ;
        RECT 1579.560000 1769.460000 2010.500000 1771.260000 ;
        RECT 1579.560000 1740.300000 2010.500000 1742.100000 ;
        RECT 1520.400000 1754.400000 2564.600000 1757.760000 ;
        RECT 1520.400000 1591.200000 1581.360000 1594.560000 ;
        RECT 1520.400000 1645.600000 1581.360000 1648.960000 ;
        RECT 1520.400000 1700.000000 1581.360000 1703.360000 ;
        RECT 1520.400000 1808.800000 1581.360000 1812.160000 ;
        RECT 1520.400000 1863.200000 1581.360000 1866.560000 ;
        RECT 1520.400000 1917.600000 1581.360000 1920.960000 ;
        RECT 2008.700000 1319.200000 2039.660000 1322.560000 ;
        RECT 2008.700000 1373.600000 2039.660000 1376.960000 ;
        RECT 2008.700000 1428.000000 2039.660000 1431.360000 ;
        RECT 2008.700000 1482.400000 2039.660000 1485.760000 ;
        RECT 2008.700000 1536.800000 2039.660000 1540.160000 ;
        RECT 2008.700000 1591.200000 2039.660000 1594.560000 ;
        RECT 2467.000000 1319.200000 2564.600000 1322.560000 ;
        RECT 2467.000000 1373.600000 2564.600000 1376.960000 ;
        RECT 2467.000000 1428.000000 2564.600000 1431.360000 ;
        RECT 2467.000000 1482.400000 2564.600000 1485.760000 ;
        RECT 2467.000000 1536.800000 2564.600000 1540.160000 ;
        RECT 2467.000000 1591.200000 2564.600000 1594.560000 ;
        RECT 2037.860000 1769.460000 2468.800000 1771.260000 ;
        RECT 2037.860000 1740.300000 2468.800000 1742.100000 ;
        RECT 2008.700000 1645.600000 2039.660000 1648.960000 ;
        RECT 2008.700000 1700.000000 2039.660000 1703.360000 ;
        RECT 2008.700000 1808.800000 2039.660000 1812.160000 ;
        RECT 2008.700000 1863.200000 2039.660000 1866.560000 ;
        RECT 2008.700000 1917.600000 2039.660000 1920.960000 ;
        RECT 2467.000000 1645.600000 2564.600000 1648.960000 ;
        RECT 2467.000000 1700.000000 2564.600000 1703.360000 ;
        RECT 2467.000000 1808.800000 2564.600000 1812.160000 ;
        RECT 2459.370000 1778.020000 2468.800000 1779.760000 ;
        RECT 2467.000000 1863.200000 2564.600000 1866.560000 ;
        RECT 2467.000000 1917.600000 2564.600000 1920.960000 ;
        RECT 1579.560000 2465.160000 2010.500000 2466.960000 ;
        RECT 1520.400000 2244.000000 1581.360000 2247.360000 ;
        RECT 1520.400000 1972.000000 1581.360000 1975.360000 ;
        RECT 1520.400000 2080.800000 1581.360000 2084.160000 ;
        RECT 1520.400000 2135.200000 1581.360000 2138.560000 ;
        RECT 1520.400000 2189.600000 1581.360000 2192.960000 ;
        RECT 1520.400000 2298.400000 1581.360000 2301.760000 ;
        RECT 1520.400000 2352.800000 1581.360000 2356.160000 ;
        RECT 1520.400000 2407.200000 1581.360000 2410.560000 ;
        RECT 1512.570000 2456.660000 1522.200000 2458.400000 ;
        RECT 1550.385000 2461.600000 1553.745000 2464.960000 ;
        RECT 2008.700000 2244.000000 2039.660000 2247.360000 ;
        RECT 2467.000000 2244.000000 2564.600000 2247.360000 ;
        RECT 2008.700000 1972.000000 2039.660000 1975.360000 ;
        RECT 2008.700000 2026.400000 2039.660000 2029.760000 ;
        RECT 2008.700000 2080.800000 2039.660000 2084.160000 ;
        RECT 2008.700000 2135.200000 2039.660000 2138.560000 ;
        RECT 2008.700000 2189.600000 2039.660000 2192.960000 ;
        RECT 2467.000000 1972.000000 2564.600000 1975.360000 ;
        RECT 2467.000000 2026.400000 2564.600000 2029.760000 ;
        RECT 2467.000000 2080.800000 2564.600000 2084.160000 ;
        RECT 2467.000000 2135.200000 2564.600000 2138.560000 ;
        RECT 2467.000000 2189.600000 2564.600000 2192.960000 ;
        RECT 2037.860000 2465.160000 2468.800000 2466.960000 ;
        RECT 2008.700000 2298.400000 2039.660000 2301.760000 ;
        RECT 2008.700000 2352.800000 2039.660000 2356.160000 ;
        RECT 2001.070000 2456.660000 2010.500000 2458.400000 ;
        RECT 2008.700000 2407.200000 2039.660000 2410.560000 ;
        RECT 2467.000000 2298.400000 2564.600000 2301.760000 ;
        RECT 2467.000000 2352.800000 2564.600000 2356.160000 ;
        RECT 2467.000000 2407.200000 2564.600000 2410.560000 ;
        RECT 2475.205000 2461.600000 2564.600000 2464.960000 ;
        RECT 1046.440000 556.300000 1048.240000 560.960000 ;
        RECT 108.400000 785.200000 110.140000 786.940000 ;
        RECT 978.780000 785.200000 980.520000 786.940000 ;
        RECT 1733.640000 106.560000 1735.380000 108.300000 ;
        RECT 1768.000000 98.000000 1773.100000 99.800000 ;
        RECT 1742.140000 556.300000 1743.940000 560.960000 ;
        RECT 1733.640000 564.860000 1735.380000 566.600000 ;
        RECT 1768.000000 556.300000 1773.100000 558.100000 ;
        RECT 1768.000000 527.140000 1773.100000 528.940000 ;
        RECT 2458.500000 106.560000 2460.240000 108.300000 ;
        RECT 2467.000000 556.300000 2468.800000 560.960000 ;
        RECT 1768.000000 985.440000 1773.100000 987.240000 ;
        RECT 2000.200000 1053.160000 2001.940000 1054.900000 ;
        RECT 2458.500000 976.940000 2460.240000 978.680000 ;
        RECT 2458.500000 1053.160000 2460.240000 1054.900000 ;
        RECT 108.400000 1510.060000 110.140000 1511.800000 ;
        RECT 978.780000 1510.060000 980.520000 1511.800000 ;
        RECT 108.400000 1998.360000 110.140000 2000.100000 ;
        RECT 81.600000 2461.600000 84.960000 2464.960000 ;
        RECT 108.400000 2456.660000 110.140000 2458.400000 ;
        RECT 833.260000 1998.360000 835.000000 2000.100000 ;
        RECT 2458.500000 1778.020000 2460.240000 1779.760000 ;
        RECT 1511.900000 2456.660000 1513.640000 2458.400000 ;
        RECT 1550.400000 2461.600000 1553.760000 2464.960000 ;
        RECT 2000.200000 2456.660000 2001.940000 2458.400000 ;
        RECT 2475.200000 2461.600000 2478.560000 2464.960000 ;
    END
# end of P/G power stripe data as pin

  END VSS
  PIN VDD
    DIRECTION INOUT ;
    USE POWER ;
    PORT
      LAYER met5 ;
        RECT 2560.480000 2540.480000 2568.640000 2548.640000 ;
    END
    PORT
      LAYER met5 ;
        RECT 0.000000 2540.480000 8.160000 2548.640000 ;
    END
    PORT
      LAYER met5 ;
        RECT 2560.480000 16.320000 2568.640000 24.480000 ;
    END
    PORT
      LAYER met5 ;
        RECT 0.000000 16.320000 8.160000 24.480000 ;
    END
    PORT
      LAYER met4 ;
        RECT 2544.200000 2556.800000 2552.360000 2564.960000 ;
    END
    PORT
      LAYER met4 ;
        RECT 2544.200000 0.000000 2552.360000 8.160000 ;
    END
    PORT
      LAYER met4 ;
        RECT 16.280000 2556.800000 24.440000 2564.960000 ;
    END
    PORT
      LAYER met4 ;
        RECT 16.280000 0.000000 24.440000 8.160000 ;
    END

# P/G power stripe data as pin
    PORT
      LAYER met4 ;
        RECT 16.280000 0.000000 24.440000 2564.960000 ;
        RECT 538.020000 16.320000 541.380000 1583.120000 ;
        RECT 40.800000 16.320000 44.160000 2548.640000 ;
        RECT 95.200000 16.320000 98.560000 2548.640000 ;
        RECT 103.440000 826.460000 105.240000 1516.760000 ;
        RECT 525.380000 826.460000 527.180000 1516.760000 ;
        RECT 561.740000 826.460000 563.540000 1516.760000 ;
        RECT 1074.400000 981.840000 1077.760000 1583.120000 ;
        RECT 1128.800000 981.840000 1132.160000 1583.120000 ;
        RECT 1183.200000 981.840000 1186.560000 1583.120000 ;
        RECT 1237.600000 981.840000 1240.960000 1583.120000 ;
        RECT 1020.000000 16.320000 1023.360000 1583.120000 ;
        RECT 983.680000 826.460000 985.480000 1516.760000 ;
        RECT 1292.000000 981.840000 1295.360000 1583.120000 ;
        RECT 1346.400000 981.840000 1349.760000 1583.120000 ;
        RECT 1400.800000 981.840000 1404.160000 1583.120000 ;
        RECT 1455.200000 981.840000 1458.560000 1583.120000 ;
        RECT 1509.600000 981.840000 1512.960000 1583.120000 ;
        RECT 1564.000000 981.840000 1567.360000 2548.640000 ;
        RECT 1583.160000 1048.200000 1584.960000 1738.500000 ;
        RECT 2544.200000 0.000000 2552.360000 2564.960000 ;
        RECT 2018.520000 981.840000 2021.880000 2548.640000 ;
        RECT 2488.800000 16.320000 2492.160000 2548.640000 ;
        RECT 2005.100000 1048.200000 2006.900000 1738.500000 ;
        RECT 2041.460000 1048.200000 2043.260000 1738.500000 ;
        RECT 2463.400000 1048.200000 2465.200000 1738.500000 ;
        RECT 983.680000 101.600000 985.480000 791.900000 ;
        RECT 561.740000 101.600000 563.540000 791.900000 ;
        RECT 525.380000 101.600000 527.180000 791.900000 ;
        RECT 103.440000 101.600000 105.240000 791.900000 ;
        RECT 1050.040000 559.900000 1051.840000 983.640000 ;
        RECT 639.200000 16.320000 642.560000 103.400000 ;
        RECT 149.600000 16.320000 152.960000 103.400000 ;
        RECT 312.800000 16.320000 316.160000 103.400000 ;
        RECT 258.400000 16.320000 261.760000 103.400000 ;
        RECT 204.000000 16.320000 207.360000 103.400000 ;
        RECT 476.000000 16.320000 479.360000 103.400000 ;
        RECT 421.600000 16.320000 424.960000 103.400000 ;
        RECT 367.200000 16.320000 370.560000 103.400000 ;
        RECT 584.800000 16.320000 588.160000 103.400000 ;
        RECT 530.400000 16.320000 533.760000 84.965000 ;
        RECT 1050.040000 101.600000 1051.840000 525.340000 ;
        RECT 802.400000 16.320000 805.760000 103.400000 ;
        RECT 748.000000 16.320000 751.360000 103.400000 ;
        RECT 693.600000 16.320000 696.960000 103.400000 ;
        RECT 911.200000 16.320000 914.560000 103.400000 ;
        RECT 856.800000 16.320000 860.160000 103.400000 ;
        RECT 1074.400000 16.320000 1077.760000 103.400000 ;
        RECT 965.600000 16.320000 968.960000 103.400000 ;
        RECT 1237.600000 16.320000 1240.960000 103.400000 ;
        RECT 1183.200000 16.320000 1186.560000 103.400000 ;
        RECT 1128.800000 16.320000 1132.160000 103.400000 ;
        RECT 1074.400000 523.540000 1077.760000 561.700000 ;
        RECT 1237.600000 523.540000 1240.960000 561.700000 ;
        RECT 1183.200000 523.540000 1186.560000 561.700000 ;
        RECT 1128.800000 523.540000 1132.160000 561.700000 ;
        RECT 639.200000 790.100000 642.560000 828.260000 ;
        RECT 312.800000 790.100000 316.160000 828.260000 ;
        RECT 258.400000 790.100000 261.760000 828.260000 ;
        RECT 204.000000 790.100000 207.360000 828.260000 ;
        RECT 149.600000 790.100000 152.960000 828.260000 ;
        RECT 94.080000 769.120000 97.440000 792.160000 ;
        RECT 367.200000 790.100000 370.560000 828.260000 ;
        RECT 421.600000 790.100000 424.960000 828.260000 ;
        RECT 476.000000 790.100000 479.360000 828.260000 ;
        RECT 584.800000 790.100000 588.160000 828.260000 ;
        RECT 552.380000 769.120000 555.740000 792.160000 ;
        RECT 533.180000 769.120000 536.540000 792.160000 ;
        RECT 802.400000 790.100000 805.760000 828.260000 ;
        RECT 693.600000 790.100000 696.960000 828.260000 ;
        RECT 748.000000 790.100000 751.360000 828.260000 ;
        RECT 911.200000 790.100000 914.560000 828.260000 ;
        RECT 856.800000 790.100000 860.160000 828.260000 ;
        RECT 965.600000 790.100000 968.960000 828.260000 ;
        RECT 991.480000 769.120000 994.840000 792.160000 ;
        RECT 2463.400000 559.900000 2465.200000 983.640000 ;
        RECT 1774.900000 559.900000 1776.700000 983.640000 ;
        RECT 1738.540000 559.900000 1740.340000 983.640000 ;
        RECT 1751.520000 16.320000 1754.880000 1050.000000 ;
        RECT 1774.900000 101.600000 1776.700000 525.340000 ;
        RECT 1738.540000 101.600000 1740.340000 525.340000 ;
        RECT 1400.800000 16.320000 1404.160000 103.400000 ;
        RECT 1346.400000 16.320000 1349.760000 103.400000 ;
        RECT 1292.000000 16.320000 1295.360000 103.400000 ;
        RECT 1564.000000 16.320000 1567.360000 103.400000 ;
        RECT 1509.600000 16.320000 1512.960000 103.400000 ;
        RECT 1455.200000 16.320000 1458.560000 103.400000 ;
        RECT 1727.200000 16.320000 1730.560000 103.400000 ;
        RECT 1672.800000 16.320000 1676.160000 103.400000 ;
        RECT 1618.400000 16.320000 1621.760000 103.400000 ;
        RECT 1890.400000 16.320000 1893.760000 103.400000 ;
        RECT 1836.000000 16.320000 1839.360000 103.400000 ;
        RECT 1781.600000 16.320000 1784.960000 103.400000 ;
        RECT 1400.800000 523.540000 1404.160000 561.700000 ;
        RECT 1346.400000 523.540000 1349.760000 561.700000 ;
        RECT 1292.000000 523.540000 1295.360000 561.700000 ;
        RECT 1564.000000 523.540000 1567.360000 561.700000 ;
        RECT 1509.600000 523.540000 1512.960000 561.700000 ;
        RECT 1455.200000 523.540000 1458.560000 561.700000 ;
        RECT 1727.200000 523.540000 1730.560000 561.700000 ;
        RECT 1672.800000 523.540000 1676.160000 561.700000 ;
        RECT 1618.400000 523.540000 1621.760000 561.700000 ;
        RECT 1890.400000 523.540000 1893.760000 561.700000 ;
        RECT 1836.000000 523.540000 1839.360000 561.700000 ;
        RECT 1781.600000 523.540000 1784.960000 561.700000 ;
        RECT 2463.400000 101.600000 2465.200000 525.340000 ;
        RECT 2053.600000 16.320000 2056.960000 103.400000 ;
        RECT 2018.520000 16.320000 2021.880000 103.400000 ;
        RECT 1999.200000 16.320000 2002.560000 103.400000 ;
        RECT 1944.800000 16.320000 1948.160000 103.400000 ;
        RECT 2216.800000 16.320000 2220.160000 103.400000 ;
        RECT 2162.400000 16.320000 2165.760000 103.400000 ;
        RECT 2108.000000 16.320000 2111.360000 103.400000 ;
        RECT 2380.000000 16.320000 2383.360000 103.400000 ;
        RECT 2325.600000 16.320000 2328.960000 103.400000 ;
        RECT 2271.200000 16.320000 2274.560000 103.400000 ;
        RECT 2434.400000 16.320000 2437.760000 103.400000 ;
        RECT 2053.600000 523.540000 2056.960000 561.700000 ;
        RECT 2018.520000 523.540000 2021.880000 561.700000 ;
        RECT 1999.200000 523.540000 2002.560000 561.700000 ;
        RECT 1944.800000 523.540000 1948.160000 561.700000 ;
        RECT 2216.800000 523.540000 2220.160000 561.700000 ;
        RECT 2162.400000 523.540000 2165.760000 561.700000 ;
        RECT 2108.000000 523.540000 2111.360000 561.700000 ;
        RECT 2380.000000 523.540000 2383.360000 561.700000 ;
        RECT 2325.600000 523.540000 2328.960000 561.700000 ;
        RECT 2271.200000 523.540000 2274.560000 561.700000 ;
        RECT 2434.400000 523.540000 2437.760000 561.700000 ;
        RECT 1727.200000 981.840000 1730.560000 1050.000000 ;
        RECT 1672.800000 981.840000 1676.160000 1050.000000 ;
        RECT 1618.400000 981.840000 1621.760000 1050.000000 ;
        RECT 1890.400000 981.840000 1893.760000 1050.000000 ;
        RECT 1836.000000 981.840000 1839.360000 1050.000000 ;
        RECT 1781.600000 981.840000 1784.960000 1050.000000 ;
        RECT 2053.600000 981.840000 2056.960000 1050.000000 ;
        RECT 1999.200000 981.840000 2002.560000 1050.000000 ;
        RECT 1944.800000 981.840000 1948.160000 1050.000000 ;
        RECT 2216.800000 981.840000 2220.160000 1050.000000 ;
        RECT 2162.400000 981.840000 2165.760000 1050.000000 ;
        RECT 2108.000000 981.840000 2111.360000 1050.000000 ;
        RECT 2380.000000 981.840000 2383.360000 1050.000000 ;
        RECT 2325.600000 981.840000 2328.960000 1050.000000 ;
        RECT 2271.200000 981.840000 2274.560000 1050.000000 ;
        RECT 2434.400000 981.840000 2437.760000 1050.000000 ;
        RECT 828.300000 1581.320000 830.100000 2005.060000 ;
        RECT 791.940000 1581.320000 793.740000 2005.060000 ;
        RECT 103.440000 1581.320000 105.240000 2005.060000 ;
        RECT 802.400000 1514.960000 805.760000 2548.640000 ;
        RECT 639.200000 1514.960000 642.560000 1583.120000 ;
        RECT 149.600000 1514.960000 152.960000 1583.120000 ;
        RECT 312.800000 1514.960000 316.160000 1583.120000 ;
        RECT 258.400000 1514.960000 261.760000 1583.120000 ;
        RECT 204.000000 1514.960000 207.360000 1583.120000 ;
        RECT 476.000000 1514.960000 479.360000 1583.120000 ;
        RECT 421.600000 1514.960000 424.960000 1583.120000 ;
        RECT 367.200000 1514.960000 370.560000 1583.120000 ;
        RECT 584.800000 1514.960000 588.160000 1583.120000 ;
        RECT 530.400000 1550.375000 533.760000 1583.120000 ;
        RECT 748.000000 1514.960000 751.360000 1583.120000 ;
        RECT 693.600000 1514.960000 696.960000 1583.120000 ;
        RECT 911.200000 1514.960000 914.560000 1583.120000 ;
        RECT 856.800000 1514.960000 860.160000 1583.120000 ;
        RECT 965.600000 1514.960000 968.960000 1583.120000 ;
        RECT 639.200000 2003.260000 642.560000 2041.420000 ;
        RECT 639.200000 2461.560000 642.560000 2548.640000 ;
        RECT 103.440000 2039.620000 105.240000 2463.360000 ;
        RECT 149.600000 2003.260000 152.960000 2041.420000 ;
        RECT 312.800000 2003.260000 316.160000 2041.420000 ;
        RECT 258.400000 2003.260000 261.760000 2041.420000 ;
        RECT 204.000000 2003.260000 207.360000 2041.420000 ;
        RECT 476.000000 2003.260000 479.360000 2041.420000 ;
        RECT 421.600000 2003.260000 424.960000 2041.420000 ;
        RECT 367.200000 2003.260000 370.560000 2041.420000 ;
        RECT 584.800000 2003.260000 588.160000 2041.420000 ;
        RECT 538.020000 2003.260000 541.380000 2041.420000 ;
        RECT 530.400000 2003.260000 533.760000 2041.420000 ;
        RECT 149.600000 2461.560000 152.960000 2548.640000 ;
        RECT 312.800000 2461.560000 316.160000 2548.640000 ;
        RECT 258.400000 2461.560000 261.760000 2548.640000 ;
        RECT 204.000000 2461.560000 207.360000 2548.640000 ;
        RECT 476.000000 2461.560000 479.360000 2548.640000 ;
        RECT 421.600000 2461.560000 424.960000 2548.640000 ;
        RECT 367.200000 2461.560000 370.560000 2548.640000 ;
        RECT 584.800000 2461.560000 588.160000 2548.640000 ;
        RECT 538.020000 2461.560000 541.380000 2548.640000 ;
        RECT 530.400000 2461.560000 533.760000 2548.640000 ;
        RECT 828.300000 2039.620000 830.100000 2463.360000 ;
        RECT 791.940000 2039.620000 793.740000 2463.360000 ;
        RECT 748.000000 2003.260000 751.360000 2041.420000 ;
        RECT 693.600000 2003.260000 696.960000 2041.420000 ;
        RECT 911.200000 2003.260000 914.560000 2041.420000 ;
        RECT 856.800000 2003.260000 860.160000 2041.420000 ;
        RECT 1074.400000 2003.260000 1077.760000 2041.420000 ;
        RECT 1020.000000 2003.260000 1023.360000 2041.420000 ;
        RECT 965.600000 2003.260000 968.960000 2041.420000 ;
        RECT 1237.600000 2003.260000 1240.960000 2041.420000 ;
        RECT 1183.200000 2003.260000 1186.560000 2041.420000 ;
        RECT 1128.800000 2003.260000 1132.160000 2041.420000 ;
        RECT 748.000000 2461.560000 751.360000 2548.640000 ;
        RECT 693.600000 2461.560000 696.960000 2548.640000 ;
        RECT 911.200000 2461.560000 914.560000 2548.640000 ;
        RECT 856.800000 2461.560000 860.160000 2548.640000 ;
        RECT 1074.400000 2461.560000 1077.760000 2548.640000 ;
        RECT 1020.000000 2461.560000 1023.360000 2548.640000 ;
        RECT 965.600000 2461.560000 968.960000 2548.640000 ;
        RECT 1237.600000 2461.560000 1240.960000 2548.640000 ;
        RECT 1183.200000 2461.560000 1186.560000 2548.640000 ;
        RECT 1128.800000 2461.560000 1132.160000 2548.640000 ;
        RECT 2463.400000 1773.060000 2465.200000 2463.360000 ;
        RECT 2041.460000 1773.060000 2043.260000 2463.360000 ;
        RECT 2005.100000 1773.060000 2006.900000 2463.360000 ;
        RECT 1583.160000 1773.060000 1584.960000 2463.360000 ;
        RECT 1516.800000 1581.320000 1518.600000 2005.060000 ;
        RECT 1618.400000 1736.700000 1621.760000 1774.860000 ;
        RECT 1672.800000 1736.700000 1676.160000 1774.860000 ;
        RECT 1727.200000 1736.700000 1730.560000 1774.860000 ;
        RECT 1751.520000 1736.700000 1754.880000 1774.860000 ;
        RECT 1890.400000 1736.700000 1893.760000 1774.860000 ;
        RECT 1781.600000 1736.700000 1784.960000 1774.860000 ;
        RECT 1836.000000 1736.700000 1839.360000 1774.860000 ;
        RECT 2216.800000 1736.700000 2220.160000 1774.860000 ;
        RECT 2162.400000 1736.700000 2165.760000 1774.860000 ;
        RECT 2108.000000 1736.700000 2111.360000 1774.860000 ;
        RECT 2053.600000 1736.700000 2056.960000 1774.860000 ;
        RECT 1999.200000 1736.700000 2002.560000 1774.860000 ;
        RECT 1944.800000 1736.700000 1948.160000 1774.860000 ;
        RECT 2434.400000 1736.700000 2437.760000 1774.860000 ;
        RECT 2380.000000 1736.700000 2383.360000 1774.860000 ;
        RECT 2325.600000 1736.700000 2328.960000 1774.860000 ;
        RECT 2271.200000 1736.700000 2274.560000 1774.860000 ;
        RECT 1516.800000 2039.620000 1518.600000 2463.360000 ;
        RECT 1400.800000 2003.260000 1404.160000 2041.420000 ;
        RECT 1346.400000 2003.260000 1349.760000 2041.420000 ;
        RECT 1292.000000 2003.260000 1295.360000 2041.420000 ;
        RECT 1509.600000 2003.260000 1512.960000 2041.420000 ;
        RECT 1455.200000 2003.260000 1458.560000 2041.420000 ;
        RECT 1400.800000 2461.560000 1404.160000 2548.640000 ;
        RECT 1346.400000 2461.560000 1349.760000 2548.640000 ;
        RECT 1292.000000 2461.560000 1295.360000 2548.640000 ;
        RECT 1509.600000 2461.560000 1512.960000 2548.640000 ;
        RECT 1455.200000 2461.560000 1458.560000 2548.640000 ;
        RECT 1751.520000 2461.560000 1754.880000 2548.640000 ;
        RECT 1727.200000 2461.560000 1730.560000 2548.640000 ;
        RECT 1672.800000 2461.560000 1676.160000 2548.640000 ;
        RECT 1618.400000 2461.560000 1621.760000 2548.640000 ;
        RECT 1890.400000 2461.560000 1893.760000 2548.640000 ;
        RECT 1836.000000 2461.560000 1839.360000 2548.640000 ;
        RECT 1781.600000 2461.560000 1784.960000 2548.640000 ;
        RECT 2053.600000 2461.560000 2056.960000 2548.640000 ;
        RECT 1999.200000 2461.560000 2002.560000 2548.640000 ;
        RECT 1944.800000 2461.560000 1948.160000 2548.640000 ;
        RECT 2216.800000 2461.560000 2220.160000 2548.640000 ;
        RECT 2162.400000 2461.560000 2165.760000 2548.640000 ;
        RECT 2108.000000 2461.560000 2111.360000 2548.640000 ;
        RECT 2380.000000 2461.560000 2383.360000 2548.640000 ;
        RECT 2325.600000 2461.560000 2328.960000 2548.640000 ;
        RECT 2271.200000 2461.560000 2274.560000 2548.640000 ;
        RECT 2434.400000 2461.560000 2437.760000 2548.640000 ;
        RECT 111.800000 109.960000 113.540000 111.700000 ;
        RECT 94.080000 769.120000 98.560000 772.480000 ;
        RECT 111.800000 834.820000 113.540000 836.560000 ;
        RECT 975.380000 781.800000 977.120000 783.540000 ;
        RECT 975.380000 834.820000 977.120000 836.560000 ;
        RECT 1730.240000 515.240000 1731.980000 516.980000 ;
        RECT 1783.260000 515.240000 1785.000000 516.980000 ;
        RECT 1591.520000 1056.560000 1593.260000 1058.300000 ;
        RECT 1730.240000 973.540000 1731.980000 975.280000 ;
        RECT 1783.260000 973.540000 1785.000000 975.280000 ;
        RECT 2455.100000 1056.560000 2456.840000 1058.300000 ;
        RECT 111.800000 1994.960000 113.540000 1996.700000 ;
        RECT 111.800000 2453.260000 113.540000 2455.000000 ;
        RECT 836.660000 2453.260000 838.400000 2455.000000 ;
        RECT 1591.520000 1781.420000 1593.260000 1783.160000 ;
        RECT 1508.500000 1994.960000 1510.240000 1996.700000 ;
        RECT 2455.100000 2453.260000 2456.840000 2455.000000 ;
      LAYER met5 ;
        RECT 0.000000 16.320000 2568.640000 24.480000 ;
        RECT 16.280000 27.200000 2552.360000 30.560000 ;
        RECT 1050.040000 101.600000 1740.340000 103.400000 ;
        RECT 16.280000 81.600000 2552.360000 84.960000 ;
        RECT 1050.040000 559.900000 1740.340000 561.700000 ;
        RECT 1050.040000 523.540000 1740.340000 525.340000 ;
        RECT 1050.040000 981.840000 1740.340000 983.640000 ;
        RECT 983.680000 1006.400000 2552.360000 1009.760000 ;
        RECT 983.680000 1060.800000 1584.960000 1064.160000 ;
        RECT 983.680000 1115.200000 1584.960000 1118.560000 ;
        RECT 983.680000 1169.600000 1584.960000 1172.960000 ;
        RECT 983.680000 1224.000000 1584.960000 1227.360000 ;
        RECT 983.680000 1278.400000 1584.960000 1281.760000 ;
        RECT 561.740000 101.600000 985.480000 103.400000 ;
        RECT 103.440000 101.600000 527.180000 103.400000 ;
        RECT 16.280000 136.000000 105.240000 139.360000 ;
        RECT 103.440000 109.960000 112.670000 111.700000 ;
        RECT 16.280000 190.400000 105.240000 193.760000 ;
        RECT 16.280000 244.800000 105.240000 248.160000 ;
        RECT 16.280000 299.200000 105.240000 302.560000 ;
        RECT 525.380000 136.000000 563.540000 139.360000 ;
        RECT 525.380000 190.400000 563.540000 193.760000 ;
        RECT 525.380000 299.200000 563.540000 302.560000 ;
        RECT 525.380000 244.800000 563.540000 248.160000 ;
        RECT 16.280000 353.600000 105.240000 356.960000 ;
        RECT 16.280000 408.000000 105.240000 411.360000 ;
        RECT 16.280000 462.400000 105.240000 465.760000 ;
        RECT 16.280000 516.800000 105.240000 520.160000 ;
        RECT 16.280000 571.200000 105.240000 574.560000 ;
        RECT 16.280000 625.600000 105.240000 628.960000 ;
        RECT 525.380000 353.600000 563.540000 356.960000 ;
        RECT 525.380000 462.400000 563.540000 465.760000 ;
        RECT 525.380000 408.000000 563.540000 411.360000 ;
        RECT 525.380000 516.800000 563.540000 520.160000 ;
        RECT 525.380000 625.600000 563.540000 628.960000 ;
        RECT 525.380000 571.200000 563.540000 574.560000 ;
        RECT 983.680000 136.000000 1051.840000 139.360000 ;
        RECT 983.680000 190.400000 1051.840000 193.760000 ;
        RECT 983.680000 299.200000 1051.840000 302.560000 ;
        RECT 983.680000 244.800000 1051.840000 248.160000 ;
        RECT 983.680000 353.600000 1051.840000 356.960000 ;
        RECT 983.680000 462.400000 1051.840000 465.760000 ;
        RECT 983.680000 408.000000 1051.840000 411.360000 ;
        RECT 983.680000 516.800000 1051.840000 520.160000 ;
        RECT 983.680000 625.600000 1051.840000 628.960000 ;
        RECT 983.680000 571.200000 1051.840000 574.560000 ;
        RECT 561.740000 826.460000 985.480000 828.260000 ;
        RECT 561.740000 790.100000 985.480000 791.900000 ;
        RECT 103.440000 826.460000 527.180000 828.260000 ;
        RECT 103.440000 790.100000 527.180000 791.900000 ;
        RECT 16.280000 680.000000 105.240000 683.360000 ;
        RECT 16.280000 734.400000 105.240000 737.760000 ;
        RECT 16.280000 788.800000 97.440000 792.160000 ;
        RECT 94.080000 769.120000 105.240000 772.480000 ;
        RECT 16.280000 843.200000 105.240000 846.560000 ;
        RECT 103.440000 834.820000 112.670000 836.560000 ;
        RECT 16.280000 897.600000 105.240000 900.960000 ;
        RECT 16.280000 952.000000 105.240000 955.360000 ;
        RECT 525.380000 680.000000 563.540000 683.360000 ;
        RECT 525.380000 734.400000 563.540000 737.760000 ;
        RECT 552.380000 769.120000 563.540000 772.480000 ;
        RECT 525.380000 769.120000 536.540000 772.480000 ;
        RECT 533.180000 788.800000 555.740000 792.160000 ;
        RECT 525.380000 843.200000 563.540000 846.560000 ;
        RECT 525.380000 952.000000 563.540000 955.360000 ;
        RECT 525.380000 897.600000 563.540000 900.960000 ;
        RECT 16.280000 1006.400000 105.240000 1009.760000 ;
        RECT 16.280000 1060.800000 105.240000 1064.160000 ;
        RECT 16.280000 1115.200000 105.240000 1118.560000 ;
        RECT 16.280000 1169.600000 105.240000 1172.960000 ;
        RECT 16.280000 1224.000000 105.240000 1227.360000 ;
        RECT 16.280000 1278.400000 105.240000 1281.760000 ;
        RECT 525.380000 1006.400000 563.540000 1009.760000 ;
        RECT 525.380000 1115.200000 563.540000 1118.560000 ;
        RECT 525.380000 1060.800000 563.540000 1064.160000 ;
        RECT 525.380000 1169.600000 563.540000 1172.960000 ;
        RECT 525.380000 1278.400000 563.540000 1281.760000 ;
        RECT 525.380000 1224.000000 563.540000 1227.360000 ;
        RECT 983.680000 680.000000 1051.840000 683.360000 ;
        RECT 983.680000 734.400000 1051.840000 737.760000 ;
        RECT 991.480000 788.800000 1051.840000 792.160000 ;
        RECT 976.250000 781.800000 985.480000 783.540000 ;
        RECT 983.680000 769.120000 994.840000 772.480000 ;
        RECT 983.680000 843.200000 1051.840000 846.560000 ;
        RECT 976.250000 834.820000 985.480000 836.560000 ;
        RECT 983.680000 952.000000 1051.840000 955.360000 ;
        RECT 983.680000 897.600000 1051.840000 900.960000 ;
        RECT 1774.900000 559.900000 2465.200000 561.700000 ;
        RECT 1774.900000 523.540000 2465.200000 525.340000 ;
        RECT 1774.900000 101.600000 2465.200000 103.400000 ;
        RECT 1738.540000 136.000000 1776.700000 139.360000 ;
        RECT 1738.540000 190.400000 1776.700000 193.760000 ;
        RECT 1738.540000 244.800000 1776.700000 248.160000 ;
        RECT 1738.540000 299.200000 1776.700000 302.560000 ;
        RECT 1738.540000 353.600000 1776.700000 356.960000 ;
        RECT 1738.540000 408.000000 1776.700000 411.360000 ;
        RECT 1738.540000 462.400000 1776.700000 465.760000 ;
        RECT 1738.540000 516.800000 1776.700000 520.160000 ;
        RECT 1738.540000 571.200000 1776.700000 574.560000 ;
        RECT 1738.540000 625.600000 1776.700000 628.960000 ;
        RECT 1730.240000 516.110000 1731.980000 525.340000 ;
        RECT 1783.260000 516.110000 1785.000000 525.340000 ;
        RECT 2463.400000 136.000000 2552.360000 139.360000 ;
        RECT 2463.400000 190.400000 2552.360000 193.760000 ;
        RECT 2463.400000 244.800000 2552.360000 248.160000 ;
        RECT 2463.400000 299.200000 2552.360000 302.560000 ;
        RECT 2463.400000 353.600000 2552.360000 356.960000 ;
        RECT 2463.400000 408.000000 2552.360000 411.360000 ;
        RECT 2463.400000 462.400000 2552.360000 465.760000 ;
        RECT 2463.400000 516.800000 2552.360000 520.160000 ;
        RECT 2463.400000 571.200000 2552.360000 574.560000 ;
        RECT 2463.400000 625.600000 2552.360000 628.960000 ;
        RECT 1774.900000 981.840000 2465.200000 983.640000 ;
        RECT 1583.160000 1048.200000 2006.900000 1050.000000 ;
        RECT 1738.540000 680.000000 1776.700000 683.360000 ;
        RECT 1738.540000 734.400000 1776.700000 737.760000 ;
        RECT 1738.540000 788.800000 1776.700000 792.160000 ;
        RECT 1738.540000 843.200000 1776.700000 846.560000 ;
        RECT 1738.540000 897.600000 1776.700000 900.960000 ;
        RECT 1738.540000 952.000000 1776.700000 955.360000 ;
        RECT 1583.160000 1056.560000 1592.390000 1058.300000 ;
        RECT 1730.240000 974.410000 1731.980000 983.640000 ;
        RECT 1783.260000 974.410000 1785.000000 983.640000 ;
        RECT 2463.400000 680.000000 2552.360000 683.360000 ;
        RECT 2463.400000 734.400000 2552.360000 737.760000 ;
        RECT 2463.400000 788.800000 2552.360000 792.160000 ;
        RECT 2463.400000 843.200000 2552.360000 846.560000 ;
        RECT 2463.400000 897.600000 2552.360000 900.960000 ;
        RECT 2463.400000 952.000000 2552.360000 955.360000 ;
        RECT 2041.460000 1048.200000 2465.200000 1050.000000 ;
        RECT 2005.100000 1115.200000 2043.260000 1118.560000 ;
        RECT 2005.100000 1060.800000 2043.260000 1064.160000 ;
        RECT 2005.100000 1169.600000 2043.260000 1172.960000 ;
        RECT 2005.100000 1278.400000 2043.260000 1281.760000 ;
        RECT 2005.100000 1224.000000 2043.260000 1227.360000 ;
        RECT 2463.400000 1060.800000 2552.360000 1064.160000 ;
        RECT 2463.400000 1115.200000 2552.360000 1118.560000 ;
        RECT 2455.970000 1056.560000 2465.200000 1058.300000 ;
        RECT 2463.400000 1169.600000 2552.360000 1172.960000 ;
        RECT 2463.400000 1224.000000 2552.360000 1227.360000 ;
        RECT 2463.400000 1278.400000 2552.360000 1281.760000 ;
        RECT 983.680000 1441.600000 1584.960000 1444.960000 ;
        RECT 983.680000 1332.800000 1584.960000 1336.160000 ;
        RECT 983.680000 1387.200000 1584.960000 1390.560000 ;
        RECT 983.680000 1496.000000 1584.960000 1499.360000 ;
        RECT 828.300000 1581.320000 1518.600000 1583.120000 ;
        RECT 16.280000 1550.400000 1584.960000 1553.760000 ;
        RECT 828.300000 2039.620000 1518.600000 2041.420000 ;
        RECT 828.300000 2003.260000 1518.600000 2005.060000 ;
        RECT 828.300000 2461.560000 1518.600000 2463.360000 ;
        RECT 16.280000 2475.200000 2552.360000 2478.560000 ;
        RECT 0.000000 2540.480000 2568.640000 2548.640000 ;
        RECT 16.280000 2529.600000 2552.360000 2532.960000 ;
        RECT 561.740000 1514.960000 985.480000 1516.760000 ;
        RECT 103.440000 1581.320000 793.740000 1583.120000 ;
        RECT 103.440000 1514.960000 527.180000 1516.760000 ;
        RECT 16.280000 1441.600000 105.240000 1444.960000 ;
        RECT 16.280000 1332.800000 105.240000 1336.160000 ;
        RECT 16.280000 1387.200000 105.240000 1390.560000 ;
        RECT 16.280000 1496.000000 105.240000 1499.360000 ;
        RECT 525.380000 1441.600000 563.540000 1444.960000 ;
        RECT 525.380000 1332.800000 563.540000 1336.160000 ;
        RECT 525.380000 1387.200000 563.540000 1390.560000 ;
        RECT 525.380000 1496.000000 563.540000 1499.360000 ;
        RECT 16.280000 1604.800000 105.240000 1608.160000 ;
        RECT 16.280000 1659.200000 105.240000 1662.560000 ;
        RECT 16.280000 1713.600000 105.240000 1716.960000 ;
        RECT 16.280000 1768.000000 105.240000 1771.360000 ;
        RECT 16.280000 1822.400000 105.240000 1825.760000 ;
        RECT 16.280000 1876.800000 105.240000 1880.160000 ;
        RECT 791.940000 1604.800000 830.100000 1608.160000 ;
        RECT 791.940000 1659.200000 830.100000 1662.560000 ;
        RECT 791.940000 1713.600000 830.100000 1716.960000 ;
        RECT 791.940000 1768.000000 830.100000 1771.360000 ;
        RECT 791.940000 1822.400000 830.100000 1825.760000 ;
        RECT 791.940000 1876.800000 830.100000 1880.160000 ;
        RECT 103.440000 2003.260000 793.740000 2005.060000 ;
        RECT 103.440000 2039.620000 793.740000 2041.420000 ;
        RECT 103.440000 2461.560000 793.740000 2463.360000 ;
        RECT 16.280000 1931.200000 105.240000 1934.560000 ;
        RECT 16.280000 1985.600000 105.240000 1988.960000 ;
        RECT 103.440000 1994.960000 112.870000 1996.700000 ;
        RECT 16.280000 2040.000000 105.240000 2043.360000 ;
        RECT 16.280000 2094.400000 105.240000 2097.760000 ;
        RECT 16.280000 2148.800000 105.240000 2152.160000 ;
        RECT 16.280000 2203.200000 105.240000 2206.560000 ;
        RECT 16.280000 2257.600000 105.240000 2260.960000 ;
        RECT 16.280000 2312.000000 105.240000 2315.360000 ;
        RECT 16.280000 2366.400000 105.240000 2369.760000 ;
        RECT 16.280000 2420.800000 105.240000 2424.160000 ;
        RECT 103.440000 2453.260000 112.870000 2455.000000 ;
        RECT 791.940000 1931.200000 830.100000 1934.560000 ;
        RECT 791.940000 1985.600000 830.100000 1988.960000 ;
        RECT 791.940000 2040.000000 830.100000 2043.360000 ;
        RECT 791.940000 2094.400000 830.100000 2097.760000 ;
        RECT 791.940000 2148.800000 830.100000 2152.160000 ;
        RECT 791.940000 2203.200000 830.100000 2206.560000 ;
        RECT 791.940000 2257.600000 830.100000 2260.960000 ;
        RECT 791.940000 2312.000000 830.100000 2315.360000 ;
        RECT 791.940000 2366.400000 830.100000 2369.760000 ;
        RECT 791.940000 2420.800000 830.100000 2424.160000 ;
        RECT 836.660000 2454.130000 838.400000 2463.360000 ;
        RECT 1583.160000 1773.060000 2006.900000 1774.860000 ;
        RECT 1583.160000 1736.700000 2006.900000 1738.500000 ;
        RECT 1516.800000 1659.200000 1584.960000 1662.560000 ;
        RECT 1516.800000 1604.800000 1584.960000 1608.160000 ;
        RECT 1516.800000 1713.600000 1584.960000 1716.960000 ;
        RECT 1516.800000 1822.400000 1584.960000 1825.760000 ;
        RECT 1516.800000 1768.000000 1567.355000 1771.360000 ;
        RECT 1583.160000 1781.420000 1592.390000 1783.160000 ;
        RECT 1516.800000 1876.800000 1584.960000 1880.160000 ;
        RECT 2005.100000 1441.600000 2043.260000 1444.960000 ;
        RECT 2005.100000 1332.800000 2043.260000 1336.160000 ;
        RECT 2005.100000 1387.200000 2043.260000 1390.560000 ;
        RECT 2005.100000 1496.000000 2043.260000 1499.360000 ;
        RECT 2005.100000 1550.400000 2043.260000 1553.760000 ;
        RECT 2463.400000 1441.600000 2552.360000 1444.960000 ;
        RECT 2463.400000 1332.800000 2552.360000 1336.160000 ;
        RECT 2463.400000 1387.200000 2552.360000 1390.560000 ;
        RECT 2463.400000 1496.000000 2552.360000 1499.360000 ;
        RECT 2463.400000 1550.400000 2552.360000 1553.760000 ;
        RECT 2041.460000 1773.060000 2465.200000 1774.860000 ;
        RECT 2041.460000 1736.700000 2465.200000 1738.500000 ;
        RECT 2005.100000 1659.200000 2043.260000 1662.560000 ;
        RECT 2005.100000 1604.800000 2043.260000 1608.160000 ;
        RECT 2005.100000 1713.600000 2043.260000 1716.960000 ;
        RECT 2005.100000 1822.400000 2043.260000 1825.760000 ;
        RECT 2005.100000 1876.800000 2043.260000 1880.160000 ;
        RECT 2463.400000 1604.800000 2552.360000 1608.160000 ;
        RECT 2463.400000 1659.200000 2552.360000 1662.560000 ;
        RECT 2463.400000 1713.600000 2552.360000 1716.960000 ;
        RECT 2463.400000 1822.400000 2552.360000 1825.760000 ;
        RECT 2488.810000 1768.000000 2552.360000 1771.360000 ;
        RECT 2463.400000 1876.800000 2552.360000 1880.160000 ;
        RECT 1583.160000 2461.560000 2006.900000 2463.360000 ;
        RECT 1508.500000 1995.830000 1510.240000 2005.060000 ;
        RECT 1516.800000 1985.600000 1584.960000 1988.960000 ;
        RECT 1516.800000 1931.200000 1584.960000 1934.560000 ;
        RECT 1516.800000 2040.000000 1584.960000 2043.360000 ;
        RECT 1516.800000 2148.800000 1584.960000 2152.160000 ;
        RECT 1516.800000 2094.400000 1584.960000 2097.760000 ;
        RECT 1516.800000 2203.200000 1584.960000 2206.560000 ;
        RECT 1516.800000 2312.000000 1584.960000 2315.360000 ;
        RECT 1516.800000 2257.600000 1584.960000 2260.960000 ;
        RECT 1516.800000 2366.400000 1584.960000 2369.760000 ;
        RECT 1516.800000 2420.800000 1584.960000 2424.160000 ;
        RECT 2005.100000 1985.600000 2043.260000 1988.960000 ;
        RECT 2005.100000 1931.200000 2043.260000 1934.560000 ;
        RECT 2005.100000 2040.000000 2043.260000 2043.360000 ;
        RECT 2005.100000 2148.800000 2043.260000 2152.160000 ;
        RECT 2005.100000 2094.400000 2043.260000 2097.760000 ;
        RECT 2005.100000 2203.200000 2043.260000 2206.560000 ;
        RECT 2463.400000 1931.200000 2552.360000 1934.560000 ;
        RECT 2463.400000 1985.600000 2552.360000 1988.960000 ;
        RECT 2463.400000 2040.000000 2552.360000 2043.360000 ;
        RECT 2463.400000 2094.400000 2552.360000 2097.760000 ;
        RECT 2463.400000 2148.800000 2552.360000 2152.160000 ;
        RECT 2463.400000 2203.200000 2552.360000 2206.560000 ;
        RECT 2041.460000 2461.560000 2465.200000 2463.360000 ;
        RECT 2005.100000 2312.000000 2043.260000 2315.360000 ;
        RECT 2005.100000 2257.600000 2043.260000 2260.960000 ;
        RECT 2005.100000 2366.400000 2043.260000 2369.760000 ;
        RECT 2005.100000 2420.800000 2043.260000 2424.160000 ;
        RECT 2463.400000 2257.600000 2552.360000 2260.960000 ;
        RECT 2463.400000 2312.000000 2552.360000 2315.360000 ;
        RECT 2463.400000 2366.400000 2552.360000 2369.760000 ;
        RECT 2463.400000 2420.800000 2552.360000 2424.160000 ;
        RECT 2455.970000 2453.260000 2465.200000 2455.000000 ;
        RECT 111.800000 109.960000 113.540000 111.700000 ;
        RECT 111.800000 834.820000 113.540000 836.560000 ;
        RECT 975.380000 781.800000 977.120000 783.540000 ;
        RECT 975.380000 834.820000 977.120000 836.560000 ;
        RECT 1730.240000 515.240000 1731.980000 516.980000 ;
        RECT 1783.260000 515.240000 1785.000000 516.980000 ;
        RECT 1591.520000 1056.560000 1593.260000 1058.300000 ;
        RECT 1730.240000 973.540000 1731.980000 975.280000 ;
        RECT 1783.260000 973.540000 1785.000000 975.280000 ;
        RECT 2455.100000 1056.560000 2456.840000 1058.300000 ;
        RECT 111.800000 1994.960000 113.540000 1996.700000 ;
        RECT 103.440000 2039.620000 105.240000 2043.360000 ;
        RECT 111.800000 2453.260000 113.540000 2455.000000 ;
        RECT 791.940000 2039.620000 793.740000 2043.360000 ;
        RECT 828.300000 2039.620000 830.100000 2043.360000 ;
        RECT 836.660000 2453.260000 838.400000 2455.000000 ;
        RECT 1564.000000 1768.000000 1567.360000 1771.360000 ;
        RECT 1591.520000 1781.420000 1593.260000 1783.160000 ;
        RECT 2488.800000 1768.000000 2492.160000 1771.360000 ;
        RECT 1508.500000 1994.960000 1510.240000 1996.700000 ;
        RECT 1516.800000 2039.620000 1518.600000 2043.360000 ;
        RECT 2455.100000 2453.260000 2456.840000 2455.000000 ;
    END
# end of P/G power stripe data as pin

  END VDD
  OBS
    LAYER li1 ;
      RECT 0.000000 0.000000 2568.640000 2564.960000 ;
    LAYER met1 ;
      RECT 0.000000 0.000000 2568.640000 2564.960000 ;
    LAYER met2 ;
      RECT 0.000000 0.000000 2568.640000 2564.960000 ;
    LAYER met3 ;
      RECT 0.000000 0.000000 2568.640000 2564.960000 ;
    LAYER met4 ;
      RECT 0.000000 0.000000 2568.640000 2564.960000 ;
    LAYER met5 ;
      RECT 0.000000 0.000000 2568.640000 2564.960000 ;
  END
END deconv_kernel_estimator_top_level

END LIBRARY
